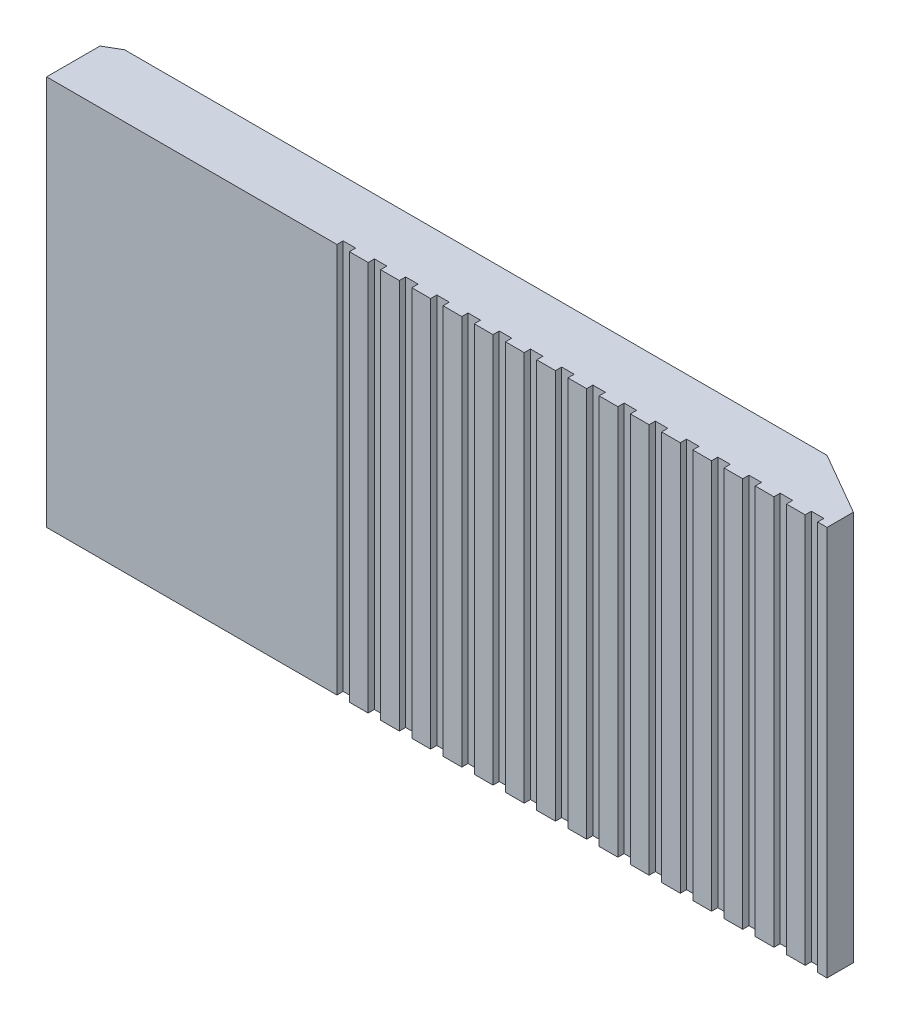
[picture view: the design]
ISO-10303-21;
HEADER;
FILE_DESCRIPTION(('STEP AP214'),'2;1');
FILE_NAME('part.step','',(''),(''),'','','');
FILE_SCHEMA(('AUTOMOTIVE_DESIGN { 1 0 10303 214 1 1 1 1 }'));
ENDSEC;
DATA;
#1=APPLICATION_CONTEXT('core data for automotive mechanical design processes');
#2=APPLICATION_PROTOCOL_DEFINITION('international standard','automotive_design',2000,#1);
#3=PRODUCT_CONTEXT('',#1,'mechanical');
#4=PRODUCT('Part','Part','',(#3));
#5=PRODUCT_RELATED_PRODUCT_CATEGORY('part','',(#4));
#6=PRODUCT_DEFINITION_FORMATION('','',#4);
#7=PRODUCT_DEFINITION_CONTEXT('part definition',#1,'design');
#8=PRODUCT_DEFINITION('design','',#6,#7);
#9=PRODUCT_DEFINITION_SHAPE('','',#8);
#10=(LENGTH_UNIT() NAMED_UNIT(*) SI_UNIT(.MILLI.,.METRE.));
#11=(NAMED_UNIT(*) PLANE_ANGLE_UNIT() SI_UNIT($,.RADIAN.));
#12=(NAMED_UNIT(*) SI_UNIT($,.STERADIAN.) SOLID_ANGLE_UNIT());
#13=UNCERTAINTY_MEASURE_WITH_UNIT(LENGTH_MEASURE(1.E-05),#10,'distance_accuracy_value','');
#14=(GEOMETRIC_REPRESENTATION_CONTEXT(3) GLOBAL_UNCERTAINTY_ASSIGNED_CONTEXT((#13)) GLOBAL_UNIT_ASSIGNED_CONTEXT((#10,
#11,#12)) REPRESENTATION_CONTEXT('',''));
#15=CARTESIAN_POINT('',(0.,0.,0.));
#16=DIRECTION('',(0.,0.,1.));
#17=DIRECTION('',(1.,0.,0.));
#18=AXIS2_PLACEMENT_3D('',#15,#16,#17);
#19=CARTESIAN_POINT('',(0.,0.,4.));
#20=DIRECTION('',(0.,0.,-1.));
#21=DIRECTION('',(-1.,0.,0.));
#22=AXIS2_PLACEMENT_3D('',#19,#20,#21);
#23=PLANE('',#22);
#24=DIRECTION('',(-1.,0.,0.));
#25=VECTOR('',#24,1.);
#26=CARTESIAN_POINT('',(-25.,12.5,4.));
#27=LINE('',#26,#25);
#28=CARTESIAN_POINT('',(23.6,12.5,4.));
#29=VERTEX_POINT('',#28);
#30=CARTESIAN_POINT('',(22.4,12.5,4.));
#31=VERTEX_POINT('',#30);
#32=EDGE_CURVE('E582',#29,#31,#27,.T.);
#33=ORIENTED_EDGE('',*,*,#32,.T.);
#34=DIRECTION('',(0.,1.,0.));
#35=VECTOR('',#34,1.);
#36=CARTESIAN_POINT('',(22.4,-12.501,4.));
#37=LINE('',#36,#35);
#38=CARTESIAN_POINT('',(22.4,-12.5,4.));
#39=VERTEX_POINT('',#38);
#40=EDGE_CURVE('E504',#39,#31,#37,.T.);
#41=ORIENTED_EDGE('',*,*,#40,.F.);
#42=DIRECTION('',(1.,0.,0.));
#43=VECTOR('',#42,1.);
#44=CARTESIAN_POINT('',(-25.,-12.5,4.));
#45=LINE('',#44,#43);
#46=CARTESIAN_POINT('',(23.6,-12.5,4.));
#47=VERTEX_POINT('',#46);
#48=EDGE_CURVE('E520',#39,#47,#45,.T.);
#49=ORIENTED_EDGE('',*,*,#48,.T.);
#50=DIRECTION('',(0.,-1.,0.));
#51=VECTOR('',#50,1.);
#52=CARTESIAN_POINT('',(23.6,-12.501,4.));
#53=LINE('',#52,#51);
#54=EDGE_CURVE('E643',#29,#47,#53,.T.);
#55=ORIENTED_EDGE('',*,*,#54,.F.);
#56=EDGE_LOOP('',(#33,#41,#49,#55));
#57=FACE_BOUND('',#56,.T.);
#58=ADVANCED_FACE('F34',(#57),#23,.F.);
#59=CARTESIAN_POINT('',(20.4,-12.5,4.));
#60=VERTEX_POINT('',#59);
#61=CARTESIAN_POINT('',(21.6,-12.5,4.));
#62=VERTEX_POINT('',#61);
#63=EDGE_CURVE('E511',#60,#62,#45,.T.);
#64=ORIENTED_EDGE('',*,*,#63,.T.);
#65=DIRECTION('',(0.,-1.,0.));
#66=VECTOR('',#65,1.);
#67=CARTESIAN_POINT('',(21.6,-12.501,4.));
#68=LINE('',#67,#66);
#69=CARTESIAN_POINT('',(21.6,12.5,4.));
#70=VERTEX_POINT('',#69);
#71=EDGE_CURVE('E493',#70,#62,#68,.T.);
#72=ORIENTED_EDGE('',*,*,#71,.F.);
#73=CARTESIAN_POINT('',(20.4,12.5,4.));
#74=VERTEX_POINT('',#73);
#75=EDGE_CURVE('E587',#70,#74,#27,.T.);
#76=ORIENTED_EDGE('',*,*,#75,.T.);
#77=DIRECTION('',(0.,1.,0.));
#78=VECTOR('',#77,1.);
#79=CARTESIAN_POINT('',(20.4,-12.501,4.));
#80=LINE('',#79,#78);
#81=EDGE_CURVE('E518',#60,#74,#80,.T.);
#82=ORIENTED_EDGE('',*,*,#81,.F.);
#83=EDGE_LOOP('',(#64,#72,#76,#82));
#84=FACE_BOUND('',#83,.T.);
#85=ADVANCED_FACE('F517',(#84),#23,.F.);
#86=CARTESIAN_POINT('',(18.4,-12.5,4.));
#87=VERTEX_POINT('',#86);
#88=CARTESIAN_POINT('',(19.6,-12.5,4.));
#89=VERTEX_POINT('',#88);
#90=EDGE_CURVE('E519',#87,#89,#45,.T.);
#91=ORIENTED_EDGE('',*,*,#90,.T.);
#92=DIRECTION('',(0.,-1.,0.));
#93=VECTOR('',#92,1.);
#94=CARTESIAN_POINT('',(19.6,-12.501,4.));
#95=LINE('',#94,#93);
#96=CARTESIAN_POINT('',(19.6,12.5,4.));
#97=VERTEX_POINT('',#96);
#98=EDGE_CURVE('E911',#97,#89,#95,.T.);
#99=ORIENTED_EDGE('',*,*,#98,.F.);
#100=CARTESIAN_POINT('',(18.4,12.5,4.));
#101=VERTEX_POINT('',#100);
#102=EDGE_CURVE('E1127',#97,#101,#27,.T.);
#103=ORIENTED_EDGE('',*,*,#102,.T.);
#104=DIRECTION('',(0.,1.,0.));
#105=VECTOR('',#104,1.);
#106=CARTESIAN_POINT('',(18.4,-12.501,4.));
#107=LINE('',#106,#105);
#108=EDGE_CURVE('E928',#87,#101,#107,.T.);
#109=ORIENTED_EDGE('',*,*,#108,.F.);
#110=EDGE_LOOP('',(#91,#99,#103,#109));
#111=FACE_BOUND('',#110,.T.);
#112=ADVANCED_FACE('F1012',(#111),#23,.F.);
#113=CARTESIAN_POINT('',(16.4,-12.5,4.));
#114=VERTEX_POINT('',#113);
#115=CARTESIAN_POINT('',(17.6,-12.5,4.));
#116=VERTEX_POINT('',#115);
#117=EDGE_CURVE('E523',#114,#116,#45,.T.);
#118=ORIENTED_EDGE('',*,*,#117,.T.);
#119=DIRECTION('',(0.,-1.,0.));
#120=VECTOR('',#119,1.);
#121=CARTESIAN_POINT('',(17.6,-12.501,4.));
#122=LINE('',#121,#120);
#123=CARTESIAN_POINT('',(17.6,12.5,4.));
#124=VERTEX_POINT('',#123);
#125=EDGE_CURVE('E889',#124,#116,#122,.T.);
#126=ORIENTED_EDGE('',*,*,#125,.F.);
#127=CARTESIAN_POINT('',(16.4,12.5,4.));
#128=VERTEX_POINT('',#127);
#129=EDGE_CURVE('E1125',#124,#128,#27,.T.);
#130=ORIENTED_EDGE('',*,*,#129,.T.);
#131=DIRECTION('',(0.,1.,0.));
#132=VECTOR('',#131,1.);
#133=CARTESIAN_POINT('',(16.4,-12.501,4.));
#134=LINE('',#133,#132);
#135=EDGE_CURVE('E906',#114,#128,#134,.T.);
#136=ORIENTED_EDGE('',*,*,#135,.F.);
#137=EDGE_LOOP('',(#118,#126,#130,#136));
#138=FACE_BOUND('',#137,.T.);
#139=ADVANCED_FACE('F1107',(#138),#23,.F.);
#140=CARTESIAN_POINT('',(14.4,-12.5,4.));
#141=VERTEX_POINT('',#140);
#142=CARTESIAN_POINT('',(15.6,-12.5,4.));
#143=VERTEX_POINT('',#142);
#144=EDGE_CURVE('E1092',#141,#143,#45,.T.);
#145=ORIENTED_EDGE('',*,*,#144,.T.);
#146=DIRECTION('',(0.,-1.,0.));
#147=VECTOR('',#146,1.);
#148=CARTESIAN_POINT('',(15.6,-12.501,4.));
#149=LINE('',#148,#147);
#150=CARTESIAN_POINT('',(15.6,12.5,4.));
#151=VERTEX_POINT('',#150);
#152=EDGE_CURVE('E867',#151,#143,#149,.T.);
#153=ORIENTED_EDGE('',*,*,#152,.F.);
#154=CARTESIAN_POINT('',(14.4,12.5,4.));
#155=VERTEX_POINT('',#154);
#156=EDGE_CURVE('E1128',#151,#155,#27,.T.);
#157=ORIENTED_EDGE('',*,*,#156,.T.);
#158=DIRECTION('',(0.,1.,0.));
#159=VECTOR('',#158,1.);
#160=CARTESIAN_POINT('',(14.4,-12.501,4.));
#161=LINE('',#160,#159);
#162=EDGE_CURVE('E884',#141,#155,#161,.T.);
#163=ORIENTED_EDGE('',*,*,#162,.F.);
#164=EDGE_LOOP('',(#145,#153,#157,#163));
#165=FACE_BOUND('',#164,.T.);
#166=ADVANCED_FACE('F1300',(#165),#23,.F.);
#167=CARTESIAN_POINT('',(12.4,-12.5,4.));
#168=VERTEX_POINT('',#167);
#169=CARTESIAN_POINT('',(13.6,-12.5,4.));
#170=VERTEX_POINT('',#169);
#171=EDGE_CURVE('E1086',#168,#170,#45,.T.);
#172=ORIENTED_EDGE('',*,*,#171,.T.);
#173=DIRECTION('',(0.,-1.,0.));
#174=VECTOR('',#173,1.);
#175=CARTESIAN_POINT('',(13.6,-12.501,4.));
#176=LINE('',#175,#174);
#177=CARTESIAN_POINT('',(13.6,12.5,4.));
#178=VERTEX_POINT('',#177);
#179=EDGE_CURVE('E845',#178,#170,#176,.T.);
#180=ORIENTED_EDGE('',*,*,#179,.F.);
#181=CARTESIAN_POINT('',(12.4,12.5,4.));
#182=VERTEX_POINT('',#181);
#183=EDGE_CURVE('E1131',#178,#182,#27,.T.);
#184=ORIENTED_EDGE('',*,*,#183,.T.);
#185=DIRECTION('',(0.,1.,0.));
#186=VECTOR('',#185,1.);
#187=CARTESIAN_POINT('',(12.4,-12.501,4.));
#188=LINE('',#187,#186);
#189=EDGE_CURVE('E862',#168,#182,#188,.T.);
#190=ORIENTED_EDGE('',*,*,#189,.F.);
#191=EDGE_LOOP('',(#172,#180,#184,#190));
#192=FACE_BOUND('',#191,.T.);
#193=ADVANCED_FACE('F1285',(#192),#23,.F.);
#194=CARTESIAN_POINT('',(10.4,-12.5,4.));
#195=VERTEX_POINT('',#194);
#196=CARTESIAN_POINT('',(11.6,-12.5,4.));
#197=VERTEX_POINT('',#196);
#198=EDGE_CURVE('E1080',#195,#197,#45,.T.);
#199=ORIENTED_EDGE('',*,*,#198,.T.);
#200=DIRECTION('',(0.,-1.,0.));
#201=VECTOR('',#200,1.);
#202=CARTESIAN_POINT('',(11.6,-12.501,4.));
#203=LINE('',#202,#201);
#204=CARTESIAN_POINT('',(11.6,12.5,4.));
#205=VERTEX_POINT('',#204);
#206=EDGE_CURVE('E823',#205,#197,#203,.T.);
#207=ORIENTED_EDGE('',*,*,#206,.F.);
#208=CARTESIAN_POINT('',(10.4,12.5,4.));
#209=VERTEX_POINT('',#208);
#210=EDGE_CURVE('E1134',#205,#209,#27,.T.);
#211=ORIENTED_EDGE('',*,*,#210,.T.);
#212=DIRECTION('',(0.,1.,0.));
#213=VECTOR('',#212,1.);
#214=CARTESIAN_POINT('',(10.4,-12.501,4.));
#215=LINE('',#214,#213);
#216=EDGE_CURVE('E840',#195,#209,#215,.T.);
#217=ORIENTED_EDGE('',*,*,#216,.F.);
#218=EDGE_LOOP('',(#199,#207,#211,#217));
#219=FACE_BOUND('',#218,.T.);
#220=ADVANCED_FACE('F1270',(#219),#23,.F.);
#221=CARTESIAN_POINT('',(8.4,-12.5,4.));
#222=VERTEX_POINT('',#221);
#223=CARTESIAN_POINT('',(9.6,-12.5,4.));
#224=VERTEX_POINT('',#223);
#225=EDGE_CURVE('E1074',#222,#224,#45,.T.);
#226=ORIENTED_EDGE('',*,*,#225,.T.);
#227=DIRECTION('',(0.,-1.,0.));
#228=VECTOR('',#227,1.);
#229=CARTESIAN_POINT('',(9.6,-12.501,4.));
#230=LINE('',#229,#228);
#231=CARTESIAN_POINT('',(9.6,12.5,4.));
#232=VERTEX_POINT('',#231);
#233=EDGE_CURVE('E801',#232,#224,#230,.T.);
#234=ORIENTED_EDGE('',*,*,#233,.F.);
#235=CARTESIAN_POINT('',(8.4,12.5,4.));
#236=VERTEX_POINT('',#235);
#237=EDGE_CURVE('E1137',#232,#236,#27,.T.);
#238=ORIENTED_EDGE('',*,*,#237,.T.);
#239=DIRECTION('',(0.,1.,0.));
#240=VECTOR('',#239,1.);
#241=CARTESIAN_POINT('',(8.4,-12.501,4.));
#242=LINE('',#241,#240);
#243=EDGE_CURVE('E818',#222,#236,#242,.T.);
#244=ORIENTED_EDGE('',*,*,#243,.F.);
#245=EDGE_LOOP('',(#226,#234,#238,#244));
#246=FACE_BOUND('',#245,.T.);
#247=ADVANCED_FACE('F1255',(#246),#23,.F.);
#248=CARTESIAN_POINT('',(6.4,-12.5,4.));
#249=VERTEX_POINT('',#248);
#250=CARTESIAN_POINT('',(7.6,-12.5,4.));
#251=VERTEX_POINT('',#250);
#252=EDGE_CURVE('E1068',#249,#251,#45,.T.);
#253=ORIENTED_EDGE('',*,*,#252,.T.);
#254=DIRECTION('',(0.,-1.,0.));
#255=VECTOR('',#254,1.);
#256=CARTESIAN_POINT('',(7.6,-12.501,4.));
#257=LINE('',#256,#255);
#258=CARTESIAN_POINT('',(7.6,12.5,4.));
#259=VERTEX_POINT('',#258);
#260=EDGE_CURVE('E779',#259,#251,#257,.T.);
#261=ORIENTED_EDGE('',*,*,#260,.F.);
#262=CARTESIAN_POINT('',(6.4,12.5,4.));
#263=VERTEX_POINT('',#262);
#264=EDGE_CURVE('E1140',#259,#263,#27,.T.);
#265=ORIENTED_EDGE('',*,*,#264,.T.);
#266=DIRECTION('',(0.,1.,0.));
#267=VECTOR('',#266,1.);
#268=CARTESIAN_POINT('',(6.4,-12.501,4.));
#269=LINE('',#268,#267);
#270=EDGE_CURVE('E796',#249,#263,#269,.T.);
#271=ORIENTED_EDGE('',*,*,#270,.F.);
#272=EDGE_LOOP('',(#253,#261,#265,#271));
#273=FACE_BOUND('',#272,.T.);
#274=ADVANCED_FACE('F1240',(#273),#23,.F.);
#275=CARTESIAN_POINT('',(4.4,-12.5,4.));
#276=VERTEX_POINT('',#275);
#277=CARTESIAN_POINT('',(5.6,-12.5,4.));
#278=VERTEX_POINT('',#277);
#279=EDGE_CURVE('E1062',#276,#278,#45,.T.);
#280=ORIENTED_EDGE('',*,*,#279,.T.);
#281=DIRECTION('',(0.,-1.,0.));
#282=VECTOR('',#281,1.);
#283=CARTESIAN_POINT('',(5.6,-12.501,4.));
#284=LINE('',#283,#282);
#285=CARTESIAN_POINT('',(5.6,12.5,4.));
#286=VERTEX_POINT('',#285);
#287=EDGE_CURVE('E757',#286,#278,#284,.T.);
#288=ORIENTED_EDGE('',*,*,#287,.F.);
#289=CARTESIAN_POINT('',(4.4,12.5,4.));
#290=VERTEX_POINT('',#289);
#291=EDGE_CURVE('E1143',#286,#290,#27,.T.);
#292=ORIENTED_EDGE('',*,*,#291,.T.);
#293=DIRECTION('',(0.,1.,0.));
#294=VECTOR('',#293,1.);
#295=CARTESIAN_POINT('',(4.4,-12.501,4.));
#296=LINE('',#295,#294);
#297=EDGE_CURVE('E774',#276,#290,#296,.T.);
#298=ORIENTED_EDGE('',*,*,#297,.F.);
#299=EDGE_LOOP('',(#280,#288,#292,#298));
#300=FACE_BOUND('',#299,.T.);
#301=ADVANCED_FACE('F1225',(#300),#23,.F.);
#302=CARTESIAN_POINT('',(2.4,-12.5,4.));
#303=VERTEX_POINT('',#302);
#304=CARTESIAN_POINT('',(3.6,-12.5,4.));
#305=VERTEX_POINT('',#304);
#306=EDGE_CURVE('E1056',#303,#305,#45,.T.);
#307=ORIENTED_EDGE('',*,*,#306,.T.);
#308=DIRECTION('',(0.,-1.,0.));
#309=VECTOR('',#308,1.);
#310=CARTESIAN_POINT('',(3.6,-12.501,4.));
#311=LINE('',#310,#309);
#312=CARTESIAN_POINT('',(3.6,12.5,4.));
#313=VERTEX_POINT('',#312);
#314=EDGE_CURVE('E735',#313,#305,#311,.T.);
#315=ORIENTED_EDGE('',*,*,#314,.F.);
#316=CARTESIAN_POINT('',(2.4,12.5,4.));
#317=VERTEX_POINT('',#316);
#318=EDGE_CURVE('E1146',#313,#317,#27,.T.);
#319=ORIENTED_EDGE('',*,*,#318,.T.);
#320=DIRECTION('',(0.,1.,0.));
#321=VECTOR('',#320,1.);
#322=CARTESIAN_POINT('',(2.4,-12.501,4.));
#323=LINE('',#322,#321);
#324=EDGE_CURVE('E752',#303,#317,#323,.T.);
#325=ORIENTED_EDGE('',*,*,#324,.F.);
#326=EDGE_LOOP('',(#307,#315,#319,#325));
#327=FACE_BOUND('',#326,.T.);
#328=ADVANCED_FACE('F1210',(#327),#23,.F.);
#329=CARTESIAN_POINT('',(0.399999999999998,-12.5,4.));
#330=VERTEX_POINT('',#329);
#331=CARTESIAN_POINT('',(1.6,-12.5,4.));
#332=VERTEX_POINT('',#331);
#333=EDGE_CURVE('E1050',#330,#332,#45,.T.);
#334=ORIENTED_EDGE('',*,*,#333,.T.);
#335=DIRECTION('',(0.,-1.,0.));
#336=VECTOR('',#335,1.);
#337=CARTESIAN_POINT('',(1.6,-12.501,4.));
#338=LINE('',#337,#336);
#339=CARTESIAN_POINT('',(1.6,12.5,4.));
#340=VERTEX_POINT('',#339);
#341=EDGE_CURVE('E713',#340,#332,#338,.T.);
#342=ORIENTED_EDGE('',*,*,#341,.F.);
#343=CARTESIAN_POINT('',(0.399999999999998,12.5,4.));
#344=VERTEX_POINT('',#343);
#345=EDGE_CURVE('E1149',#340,#344,#27,.T.);
#346=ORIENTED_EDGE('',*,*,#345,.T.);
#347=DIRECTION('',(0.,1.,0.));
#348=VECTOR('',#347,1.);
#349=CARTESIAN_POINT('',(0.399999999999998,-12.501,4.));
#350=LINE('',#349,#348);
#351=EDGE_CURVE('E730',#330,#344,#350,.T.);
#352=ORIENTED_EDGE('',*,*,#351,.F.);
#353=EDGE_LOOP('',(#334,#342,#346,#352));
#354=FACE_BOUND('',#353,.T.);
#355=ADVANCED_FACE('F1195',(#354),#23,.F.);
#356=CARTESIAN_POINT('',(-1.6,-12.5,4.));
#357=VERTEX_POINT('',#356);
#358=CARTESIAN_POINT('',(-0.400000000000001,-12.5,4.));
#359=VERTEX_POINT('',#358);
#360=EDGE_CURVE('E1045',#357,#359,#45,.T.);
#361=ORIENTED_EDGE('',*,*,#360,.T.);
#362=DIRECTION('',(0.,-1.,0.));
#363=VECTOR('',#362,1.);
#364=CARTESIAN_POINT('',(-0.400000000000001,-12.501,4.));
#365=LINE('',#364,#363);
#366=CARTESIAN_POINT('',(-0.400000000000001,12.5,4.));
#367=VERTEX_POINT('',#366);
#368=EDGE_CURVE('E691',#367,#359,#365,.T.);
#369=ORIENTED_EDGE('',*,*,#368,.F.);
#370=CARTESIAN_POINT('',(-1.6,12.5,4.));
#371=VERTEX_POINT('',#370);
#372=EDGE_CURVE('E1152',#367,#371,#27,.T.);
#373=ORIENTED_EDGE('',*,*,#372,.T.);
#374=DIRECTION('',(0.,1.,0.));
#375=VECTOR('',#374,1.);
#376=CARTESIAN_POINT('',(-1.6,-12.501,4.));
#377=LINE('',#376,#375);
#378=EDGE_CURVE('E708',#357,#371,#377,.T.);
#379=ORIENTED_EDGE('',*,*,#378,.F.);
#380=EDGE_LOOP('',(#361,#369,#373,#379));
#381=FACE_BOUND('',#380,.T.);
#382=ADVANCED_FACE('F1034',(#381),#23,.F.);
#383=CARTESIAN_POINT('',(-3.6,-12.5,4.));
#384=VERTEX_POINT('',#383);
#385=CARTESIAN_POINT('',(-2.4,-12.5,4.));
#386=VERTEX_POINT('',#385);
#387=EDGE_CURVE('E1043',#384,#386,#45,.T.);
#388=ORIENTED_EDGE('',*,*,#387,.T.);
#389=DIRECTION('',(0.,-1.,0.));
#390=VECTOR('',#389,1.);
#391=CARTESIAN_POINT('',(-2.4,-12.501,4.));
#392=LINE('',#391,#390);
#393=CARTESIAN_POINT('',(-2.4,12.5,4.));
#394=VERTEX_POINT('',#393);
#395=EDGE_CURVE('E669',#394,#386,#392,.T.);
#396=ORIENTED_EDGE('',*,*,#395,.F.);
#397=CARTESIAN_POINT('',(-3.6,12.5,4.));
#398=VERTEX_POINT('',#397);
#399=EDGE_CURVE('E591',#394,#398,#27,.T.);
#400=ORIENTED_EDGE('',*,*,#399,.T.);
#401=DIRECTION('',(0.,1.,0.));
#402=VECTOR('',#401,1.);
#403=CARTESIAN_POINT('',(-3.6,-12.501,4.));
#404=LINE('',#403,#402);
#405=EDGE_CURVE('E686',#384,#398,#404,.T.);
#406=ORIENTED_EDGE('',*,*,#405,.F.);
#407=EDGE_LOOP('',(#388,#396,#400,#406));
#408=FACE_BOUND('',#407,.T.);
#409=ADVANCED_FACE('F1029',(#408),#23,.F.);
#410=CARTESIAN_POINT('',(-5.6,-12.5,4.));
#411=VERTEX_POINT('',#410);
#412=CARTESIAN_POINT('',(-4.4,-12.5,4.));
#413=VERTEX_POINT('',#412);
#414=EDGE_CURVE('E530',#411,#413,#45,.T.);
#415=ORIENTED_EDGE('',*,*,#414,.T.);
#416=DIRECTION('',(0.,-1.,0.));
#417=VECTOR('',#416,1.);
#418=CARTESIAN_POINT('',(-4.4,-12.501,4.));
#419=LINE('',#418,#417);
#420=CARTESIAN_POINT('',(-4.4,12.5,4.));
#421=VERTEX_POINT('',#420);
#422=EDGE_CURVE('E648',#421,#413,#419,.T.);
#423=ORIENTED_EDGE('',*,*,#422,.F.);
#424=CARTESIAN_POINT('',(-5.6,12.5,4.));
#425=VERTEX_POINT('',#424);
#426=EDGE_CURVE('E589',#421,#425,#27,.T.);
#427=ORIENTED_EDGE('',*,*,#426,.T.);
#428=DIRECTION('',(0.,1.,0.));
#429=VECTOR('',#428,1.);
#430=CARTESIAN_POINT('',(-5.6,-12.501,4.));
#431=LINE('',#430,#429);
#432=EDGE_CURVE('E664',#411,#425,#431,.T.);
#433=ORIENTED_EDGE('',*,*,#432,.F.);
#434=EDGE_LOOP('',(#415,#423,#427,#433));
#435=FACE_BOUND('',#434,.T.);
#436=ADVANCED_FACE('F1024',(#435),#23,.F.);
#437=CARTESIAN_POINT('',(25.,12.5,4.));
#438=VERTEX_POINT('',#437);
#439=CARTESIAN_POINT('',(24.4,12.5,4.));
#440=VERTEX_POINT('',#439);
#441=EDGE_CURVE('E580',#438,#440,#27,.T.);
#442=ORIENTED_EDGE('',*,*,#441,.T.);
#443=DIRECTION('',(0.,1.,0.));
#444=VECTOR('',#443,1.);
#445=CARTESIAN_POINT('',(24.4,-12.501,4.));
#446=LINE('',#445,#444);
#447=CARTESIAN_POINT('',(24.4,-12.5,4.));
#448=VERTEX_POINT('',#447);
#449=EDGE_CURVE('E641',#448,#440,#446,.T.);
#450=ORIENTED_EDGE('',*,*,#449,.F.);
#451=CARTESIAN_POINT('',(25.,-12.5,4.));
#452=VERTEX_POINT('',#451);
#453=EDGE_CURVE('E524',#448,#452,#45,.T.);
#454=ORIENTED_EDGE('',*,*,#453,.T.);
#455=DIRECTION('',(0.,1.,0.));
#456=VECTOR('',#455,1.);
#457=CARTESIAN_POINT('',(25.,-12.5,4.));
#458=LINE('',#457,#456);
#459=EDGE_CURVE('E538',#452,#438,#458,.T.);
#460=ORIENTED_EDGE('',*,*,#459,.T.);
#461=EDGE_LOOP('',(#442,#450,#454,#460));
#462=FACE_BOUND('',#461,.T.);
#463=ADVANCED_FACE('F1016',(#462),#23,.F.);
#464=CARTESIAN_POINT('',(0.,0.,0.));
#465=DIRECTION('',(0.,0.,-1.));
#466=DIRECTION('',(-1.,0.,0.));
#467=AXIS2_PLACEMENT_3D('',#464,#465,#466);
#468=PLANE('',#467);
#469=DIRECTION('',(1.,0.,0.));
#470=VECTOR('',#469,1.);
#471=CARTESIAN_POINT('',(-25.,-12.5,0.));
#472=LINE('',#471,#470);
#473=CARTESIAN_POINT('',(-24.,-12.5,0.));
#474=VERTEX_POINT('',#473);
#475=CARTESIAN_POINT('',(21.,-12.5,0.));
#476=VERTEX_POINT('',#475);
#477=EDGE_CURVE('E535',#474,#476,#472,.T.);
#478=ORIENTED_EDGE('',*,*,#477,.F.);
#479=DIRECTION('',(0.,1.,0.));
#480=VECTOR('',#479,1.);
#481=CARTESIAN_POINT('',(-24.,12.5,0.));
#482=LINE('',#481,#480);
#483=CARTESIAN_POINT('',(-24.,12.5,0.));
#484=VERTEX_POINT('',#483);
#485=EDGE_CURVE('E42',#474,#484,#482,.T.);
#486=ORIENTED_EDGE('',*,*,#485,.T.);
#487=DIRECTION('',(-1.,0.,0.));
#488=VECTOR('',#487,1.);
#489=CARTESIAN_POINT('',(-25.,12.5,0.));
#490=LINE('',#489,#488);
#491=CARTESIAN_POINT('',(21.,12.5,0.));
#492=VERTEX_POINT('',#491);
#493=EDGE_CURVE('E533',#492,#484,#490,.T.);
#494=ORIENTED_EDGE('',*,*,#493,.F.);
#495=DIRECTION('',(0.,-1.,0.));
#496=VECTOR('',#495,1.);
#497=CARTESIAN_POINT('',(21.,-12.5,0.));
#498=LINE('',#497,#496);
#499=EDGE_CURVE('E554',#492,#476,#498,.T.);
#500=ORIENTED_EDGE('',*,*,#499,.T.);
#501=EDGE_LOOP('',(#478,#486,#494,#500));
#502=FACE_BOUND('',#501,.T.);
#503=DIRECTION('',(1.,0.,0.));
#504=VECTOR('',#503,1.);
#505=CARTESIAN_POINT('',(15.,5.,0.));
#506=LINE('',#505,#504);
#507=CARTESIAN_POINT('',(5.,5.,0.));
#508=VERTEX_POINT('',#507);
#509=CARTESIAN_POINT('',(15.,5.,0.));
#510=VERTEX_POINT('',#509);
#511=EDGE_CURVE('E611',#508,#510,#506,.T.);
#512=ORIENTED_EDGE('',*,*,#511,.F.);
#513=DIRECTION('',(0.,1.,0.));
#514=VECTOR('',#513,1.);
#515=CARTESIAN_POINT('',(5.,-5.,0.));
#516=LINE('',#515,#514);
#517=CARTESIAN_POINT('',(5.,-5.,0.));
#518=VERTEX_POINT('',#517);
#519=EDGE_CURVE('E613',#518,#508,#516,.T.);
#520=ORIENTED_EDGE('',*,*,#519,.F.);
#521=DIRECTION('',(-1.,0.,0.));
#522=VECTOR('',#521,1.);
#523=CARTESIAN_POINT('',(15.,-5.,0.));
#524=LINE('',#523,#522);
#525=CARTESIAN_POINT('',(15.,-5.,0.));
#526=VERTEX_POINT('',#525);
#527=EDGE_CURVE('E605',#526,#518,#524,.T.);
#528=ORIENTED_EDGE('',*,*,#527,.F.);
#529=DIRECTION('',(0.,-1.,0.));
#530=VECTOR('',#529,1.);
#531=CARTESIAN_POINT('',(15.,-5.,0.));
#532=LINE('',#531,#530);
#533=EDGE_CURVE('E608',#510,#526,#532,.T.);
#534=ORIENTED_EDGE('',*,*,#533,.F.);
#535=EDGE_LOOP('',(#512,#520,#528,#534));
#536=FACE_BOUND('',#535,.T.);
#537=ADVANCED_FACE('F998',(#502,#536),#468,.T.);
#538=CARTESIAN_POINT('',(25.,-12.5,4.));
#539=DIRECTION('',(-1.,0.,0.));
#540=DIRECTION('',(0.,0.,1.));
#541=AXIS2_PLACEMENT_3D('',#538,#539,#540);
#542=PLANE('',#541);
#543=DIRECTION('',(0.,0.,-1.));
#544=VECTOR('',#543,1.);
#545=CARTESIAN_POINT('',(25.,-12.5,4.));
#546=LINE('',#545,#544);
#547=CARTESIAN_POINT('',(25.,-12.5,2.3094010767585));
#548=VERTEX_POINT('',#547);
#549=EDGE_CURVE('E529',#452,#548,#546,.T.);
#550=ORIENTED_EDGE('',*,*,#549,.T.);
#551=DIRECTION('',(0.,1.,0.));
#552=VECTOR('',#551,1.);
#553=CARTESIAN_POINT('',(25.,12.5,2.3094010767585));
#554=LINE('',#553,#552);
#555=CARTESIAN_POINT('',(25.,12.5,2.3094010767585));
#556=VERTEX_POINT('',#555);
#557=EDGE_CURVE('E549',#548,#556,#554,.T.);
#558=ORIENTED_EDGE('',*,*,#557,.T.);
#559=DIRECTION('',(0.,0.,-1.));
#560=VECTOR('',#559,1.);
#561=CARTESIAN_POINT('',(25.,12.5,4.));
#562=LINE('',#561,#560);
#563=EDGE_CURVE('E546',#438,#556,#562,.T.);
#564=ORIENTED_EDGE('',*,*,#563,.F.);
#565=ORIENTED_EDGE('',*,*,#459,.F.);
#566=EDGE_LOOP('',(#550,#558,#564,#565));
#567=FACE_BOUND('',#566,.T.);
#568=ADVANCED_FACE('F991',(#567),#542,.F.);
#569=CARTESIAN_POINT('',(-25.,12.5,4.));
#570=DIRECTION('',(0.,-1.,0.));
#571=DIRECTION('',(0.,0.,-1.));
#572=AXIS2_PLACEMENT_3D('',#569,#570,#571);
#573=PLANE('',#572);
#574=ORIENTED_EDGE('',*,*,#493,.T.);
#575=DIRECTION('',(-0.866025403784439,0.,0.5));
#576=VECTOR('',#575,1.);
#577=CARTESIAN_POINT('',(-25.,12.5,0.57735026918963));
#578=LINE('',#577,#576);
#579=CARTESIAN_POINT('',(-25.,12.5,0.57735026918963));
#580=VERTEX_POINT('',#579);
#581=EDGE_CURVE('E11',#484,#580,#578,.T.);
#582=ORIENTED_EDGE('',*,*,#581,.T.);
#583=DIRECTION('',(0.,0.,-1.));
#584=VECTOR('',#583,1.);
#585=CARTESIAN_POINT('',(-25.,12.5,4.));
#586=LINE('',#585,#584);
#587=CARTESIAN_POINT('',(-25.,12.5,4.));
#588=VERTEX_POINT('',#587);
#589=EDGE_CURVE('E543',#588,#580,#586,.T.);
#590=ORIENTED_EDGE('',*,*,#589,.F.);
#591=CARTESIAN_POINT('',(-6.4,12.5,4.));
#592=VERTEX_POINT('',#591);
#593=EDGE_CURVE('E579',#592,#588,#27,.T.);
#594=ORIENTED_EDGE('',*,*,#593,.F.);
#595=DIRECTION('',(0.,0.,1.));
#596=VECTOR('',#595,1.);
#597=CARTESIAN_POINT('',(-6.4,12.5,4.4));
#598=LINE('',#597,#596);
#599=CARTESIAN_POINT('',(-6.4,12.5,3.6));
#600=VERTEX_POINT('',#599);
#601=EDGE_CURVE('E652',#600,#592,#598,.T.);
#602=ORIENTED_EDGE('',*,*,#601,.F.);
#603=DIRECTION('',(-1.,0.,0.));
#604=VECTOR('',#603,1.);
#605=CARTESIAN_POINT('',(-6.4,12.5,3.6));
#606=LINE('',#605,#604);
#607=CARTESIAN_POINT('',(-5.6,12.5,3.6));
#608=VERTEX_POINT('',#607);
#609=EDGE_CURVE('E655',#608,#600,#606,.T.);
#610=ORIENTED_EDGE('',*,*,#609,.F.);
#611=DIRECTION('',(0.,0.,-1.));
#612=VECTOR('',#611,1.);
#613=CARTESIAN_POINT('',(-5.6,12.5,4.4));
#614=LINE('',#613,#612);
#615=EDGE_CURVE('E658',#425,#608,#614,.T.);
#616=ORIENTED_EDGE('',*,*,#615,.F.);
#617=ORIENTED_EDGE('',*,*,#426,.F.);
#618=DIRECTION('',(0.,0.,1.));
#619=VECTOR('',#618,1.);
#620=CARTESIAN_POINT('',(-4.4,12.5,4.4));
#621=LINE('',#620,#619);
#622=CARTESIAN_POINT('',(-4.4,12.5,3.6));
#623=VERTEX_POINT('',#622);
#624=EDGE_CURVE('E673',#623,#421,#621,.T.);
#625=ORIENTED_EDGE('',*,*,#624,.F.);
#626=DIRECTION('',(-1.,0.,0.));
#627=VECTOR('',#626,1.);
#628=CARTESIAN_POINT('',(-4.4,12.5,3.6));
#629=LINE('',#628,#627);
#630=CARTESIAN_POINT('',(-3.6,12.5,3.6));
#631=VERTEX_POINT('',#630);
#632=EDGE_CURVE('E676',#631,#623,#629,.T.);
#633=ORIENTED_EDGE('',*,*,#632,.F.);
#634=DIRECTION('',(0.,0.,-1.));
#635=VECTOR('',#634,1.);
#636=CARTESIAN_POINT('',(-3.6,12.5,4.4));
#637=LINE('',#636,#635);
#638=EDGE_CURVE('E679',#398,#631,#637,.T.);
#639=ORIENTED_EDGE('',*,*,#638,.F.);
#640=ORIENTED_EDGE('',*,*,#399,.F.);
#641=DIRECTION('',(0.,0.,1.));
#642=VECTOR('',#641,1.);
#643=CARTESIAN_POINT('',(-2.4,12.5,4.4));
#644=LINE('',#643,#642);
#645=CARTESIAN_POINT('',(-2.4,12.5,3.6));
#646=VERTEX_POINT('',#645);
#647=EDGE_CURVE('E695',#646,#394,#644,.T.);
#648=ORIENTED_EDGE('',*,*,#647,.F.);
#649=DIRECTION('',(-1.,0.,0.));
#650=VECTOR('',#649,1.);
#651=CARTESIAN_POINT('',(-2.4,12.5,3.6));
#652=LINE('',#651,#650);
#653=CARTESIAN_POINT('',(-1.6,12.5,3.6));
#654=VERTEX_POINT('',#653);
#655=EDGE_CURVE('E698',#654,#646,#652,.T.);
#656=ORIENTED_EDGE('',*,*,#655,.F.);
#657=DIRECTION('',(0.,0.,-1.));
#658=VECTOR('',#657,1.);
#659=CARTESIAN_POINT('',(-1.6,12.5,4.4));
#660=LINE('',#659,#658);
#661=EDGE_CURVE('E701',#371,#654,#660,.T.);
#662=ORIENTED_EDGE('',*,*,#661,.F.);
#663=ORIENTED_EDGE('',*,*,#372,.F.);
#664=DIRECTION('',(0.,0.,1.));
#665=VECTOR('',#664,1.);
#666=CARTESIAN_POINT('',(-0.400000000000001,12.5,4.4));
#667=LINE('',#666,#665);
#668=CARTESIAN_POINT('',(-0.400000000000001,12.5,3.6));
#669=VERTEX_POINT('',#668);
#670=EDGE_CURVE('E717',#669,#367,#667,.T.);
#671=ORIENTED_EDGE('',*,*,#670,.F.);
#672=DIRECTION('',(-1.,0.,0.));
#673=VECTOR('',#672,1.);
#674=CARTESIAN_POINT('',(-0.400000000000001,12.5,3.6));
#675=LINE('',#674,#673);
#676=CARTESIAN_POINT('',(0.399999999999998,12.5,3.6));
#677=VERTEX_POINT('',#676);
#678=EDGE_CURVE('E720',#677,#669,#675,.T.);
#679=ORIENTED_EDGE('',*,*,#678,.F.);
#680=DIRECTION('',(0.,0.,-1.));
#681=VECTOR('',#680,1.);
#682=CARTESIAN_POINT('',(0.399999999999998,12.5,4.4));
#683=LINE('',#682,#681);
#684=EDGE_CURVE('E723',#344,#677,#683,.T.);
#685=ORIENTED_EDGE('',*,*,#684,.F.);
#686=ORIENTED_EDGE('',*,*,#345,.F.);
#687=DIRECTION('',(0.,0.,1.));
#688=VECTOR('',#687,1.);
#689=CARTESIAN_POINT('',(1.6,12.5,4.4));
#690=LINE('',#689,#688);
#691=CARTESIAN_POINT('',(1.6,12.5,3.6));
#692=VERTEX_POINT('',#691);
#693=EDGE_CURVE('E739',#692,#340,#690,.T.);
#694=ORIENTED_EDGE('',*,*,#693,.F.);
#695=DIRECTION('',(-1.,0.,0.));
#696=VECTOR('',#695,1.);
#697=CARTESIAN_POINT('',(1.6,12.5,3.6));
#698=LINE('',#697,#696);
#699=CARTESIAN_POINT('',(2.4,12.5,3.6));
#700=VERTEX_POINT('',#699);
#701=EDGE_CURVE('E742',#700,#692,#698,.T.);
#702=ORIENTED_EDGE('',*,*,#701,.F.);
#703=DIRECTION('',(0.,0.,-1.));
#704=VECTOR('',#703,1.);
#705=CARTESIAN_POINT('',(2.4,12.5,4.4));
#706=LINE('',#705,#704);
#707=EDGE_CURVE('E745',#317,#700,#706,.T.);
#708=ORIENTED_EDGE('',*,*,#707,.F.);
#709=ORIENTED_EDGE('',*,*,#318,.F.);
#710=DIRECTION('',(0.,0.,1.));
#711=VECTOR('',#710,1.);
#712=CARTESIAN_POINT('',(3.6,12.5,4.4));
#713=LINE('',#712,#711);
#714=CARTESIAN_POINT('',(3.6,12.5,3.6));
#715=VERTEX_POINT('',#714);
#716=EDGE_CURVE('E761',#715,#313,#713,.T.);
#717=ORIENTED_EDGE('',*,*,#716,.F.);
#718=DIRECTION('',(-1.,0.,0.));
#719=VECTOR('',#718,1.);
#720=CARTESIAN_POINT('',(3.6,12.5,3.6));
#721=LINE('',#720,#719);
#722=CARTESIAN_POINT('',(4.4,12.5,3.6));
#723=VERTEX_POINT('',#722);
#724=EDGE_CURVE('E764',#723,#715,#721,.T.);
#725=ORIENTED_EDGE('',*,*,#724,.F.);
#726=DIRECTION('',(0.,0.,-1.));
#727=VECTOR('',#726,1.);
#728=CARTESIAN_POINT('',(4.4,12.5,4.4));
#729=LINE('',#728,#727);
#730=EDGE_CURVE('E767',#290,#723,#729,.T.);
#731=ORIENTED_EDGE('',*,*,#730,.F.);
#732=ORIENTED_EDGE('',*,*,#291,.F.);
#733=DIRECTION('',(0.,0.,1.));
#734=VECTOR('',#733,1.);
#735=CARTESIAN_POINT('',(5.6,12.5,4.4));
#736=LINE('',#735,#734);
#737=CARTESIAN_POINT('',(5.6,12.5,3.6));
#738=VERTEX_POINT('',#737);
#739=EDGE_CURVE('E783',#738,#286,#736,.T.);
#740=ORIENTED_EDGE('',*,*,#739,.F.);
#741=DIRECTION('',(-1.,0.,0.));
#742=VECTOR('',#741,1.);
#743=CARTESIAN_POINT('',(5.6,12.5,3.6));
#744=LINE('',#743,#742);
#745=CARTESIAN_POINT('',(6.4,12.5,3.6));
#746=VERTEX_POINT('',#745);
#747=EDGE_CURVE('E786',#746,#738,#744,.T.);
#748=ORIENTED_EDGE('',*,*,#747,.F.);
#749=DIRECTION('',(0.,0.,-1.));
#750=VECTOR('',#749,1.);
#751=CARTESIAN_POINT('',(6.4,12.5,4.4));
#752=LINE('',#751,#750);
#753=EDGE_CURVE('E789',#263,#746,#752,.T.);
#754=ORIENTED_EDGE('',*,*,#753,.F.);
#755=ORIENTED_EDGE('',*,*,#264,.F.);
#756=DIRECTION('',(0.,0.,1.));
#757=VECTOR('',#756,1.);
#758=CARTESIAN_POINT('',(7.6,12.5,4.4));
#759=LINE('',#758,#757);
#760=CARTESIAN_POINT('',(7.6,12.5,3.6));
#761=VERTEX_POINT('',#760);
#762=EDGE_CURVE('E805',#761,#259,#759,.T.);
#763=ORIENTED_EDGE('',*,*,#762,.F.);
#764=DIRECTION('',(-1.,0.,0.));
#765=VECTOR('',#764,1.);
#766=CARTESIAN_POINT('',(7.6,12.5,3.6));
#767=LINE('',#766,#765);
#768=CARTESIAN_POINT('',(8.4,12.5,3.6));
#769=VERTEX_POINT('',#768);
#770=EDGE_CURVE('E808',#769,#761,#767,.T.);
#771=ORIENTED_EDGE('',*,*,#770,.F.);
#772=DIRECTION('',(0.,0.,-1.));
#773=VECTOR('',#772,1.);
#774=CARTESIAN_POINT('',(8.4,12.5,4.4));
#775=LINE('',#774,#773);
#776=EDGE_CURVE('E811',#236,#769,#775,.T.);
#777=ORIENTED_EDGE('',*,*,#776,.F.);
#778=ORIENTED_EDGE('',*,*,#237,.F.);
#779=DIRECTION('',(0.,0.,1.));
#780=VECTOR('',#779,1.);
#781=CARTESIAN_POINT('',(9.6,12.5,4.4));
#782=LINE('',#781,#780);
#783=CARTESIAN_POINT('',(9.6,12.5,3.6));
#784=VERTEX_POINT('',#783);
#785=EDGE_CURVE('E827',#784,#232,#782,.T.);
#786=ORIENTED_EDGE('',*,*,#785,.F.);
#787=DIRECTION('',(-1.,0.,0.));
#788=VECTOR('',#787,1.);
#789=CARTESIAN_POINT('',(9.6,12.5,3.6));
#790=LINE('',#789,#788);
#791=CARTESIAN_POINT('',(10.4,12.5,3.6));
#792=VERTEX_POINT('',#791);
#793=EDGE_CURVE('E830',#792,#784,#790,.T.);
#794=ORIENTED_EDGE('',*,*,#793,.F.);
#795=DIRECTION('',(0.,0.,-1.));
#796=VECTOR('',#795,1.);
#797=CARTESIAN_POINT('',(10.4,12.5,4.4));
#798=LINE('',#797,#796);
#799=EDGE_CURVE('E833',#209,#792,#798,.T.);
#800=ORIENTED_EDGE('',*,*,#799,.F.);
#801=ORIENTED_EDGE('',*,*,#210,.F.);
#802=DIRECTION('',(0.,0.,1.));
#803=VECTOR('',#802,1.);
#804=CARTESIAN_POINT('',(11.6,12.5,4.4));
#805=LINE('',#804,#803);
#806=CARTESIAN_POINT('',(11.6,12.5,3.6));
#807=VERTEX_POINT('',#806);
#808=EDGE_CURVE('E849',#807,#205,#805,.T.);
#809=ORIENTED_EDGE('',*,*,#808,.F.);
#810=DIRECTION('',(-1.,0.,0.));
#811=VECTOR('',#810,1.);
#812=CARTESIAN_POINT('',(11.6,12.5,3.6));
#813=LINE('',#812,#811);
#814=CARTESIAN_POINT('',(12.4,12.5,3.6));
#815=VERTEX_POINT('',#814);
#816=EDGE_CURVE('E852',#815,#807,#813,.T.);
#817=ORIENTED_EDGE('',*,*,#816,.F.);
#818=DIRECTION('',(0.,0.,-1.));
#819=VECTOR('',#818,1.);
#820=CARTESIAN_POINT('',(12.4,12.5,4.4));
#821=LINE('',#820,#819);
#822=EDGE_CURVE('E855',#182,#815,#821,.T.);
#823=ORIENTED_EDGE('',*,*,#822,.F.);
#824=ORIENTED_EDGE('',*,*,#183,.F.);
#825=DIRECTION('',(0.,0.,1.));
#826=VECTOR('',#825,1.);
#827=CARTESIAN_POINT('',(13.6,12.5,4.4));
#828=LINE('',#827,#826);
#829=CARTESIAN_POINT('',(13.6,12.5,3.6));
#830=VERTEX_POINT('',#829);
#831=EDGE_CURVE('E871',#830,#178,#828,.T.);
#832=ORIENTED_EDGE('',*,*,#831,.F.);
#833=DIRECTION('',(-1.,0.,0.));
#834=VECTOR('',#833,1.);
#835=CARTESIAN_POINT('',(13.6,12.5,3.6));
#836=LINE('',#835,#834);
#837=CARTESIAN_POINT('',(14.4,12.5,3.6));
#838=VERTEX_POINT('',#837);
#839=EDGE_CURVE('E874',#838,#830,#836,.T.);
#840=ORIENTED_EDGE('',*,*,#839,.F.);
#841=DIRECTION('',(0.,0.,-1.));
#842=VECTOR('',#841,1.);
#843=CARTESIAN_POINT('',(14.4,12.5,4.4));
#844=LINE('',#843,#842);
#845=EDGE_CURVE('E877',#155,#838,#844,.T.);
#846=ORIENTED_EDGE('',*,*,#845,.F.);
#847=ORIENTED_EDGE('',*,*,#156,.F.);
#848=DIRECTION('',(0.,0.,1.));
#849=VECTOR('',#848,1.);
#850=CARTESIAN_POINT('',(15.6,12.5,4.4));
#851=LINE('',#850,#849);
#852=CARTESIAN_POINT('',(15.6,12.5,3.6));
#853=VERTEX_POINT('',#852);
#854=EDGE_CURVE('E893',#853,#151,#851,.T.);
#855=ORIENTED_EDGE('',*,*,#854,.F.);
#856=DIRECTION('',(-1.,0.,0.));
#857=VECTOR('',#856,1.);
#858=CARTESIAN_POINT('',(15.6,12.5,3.6));
#859=LINE('',#858,#857);
#860=CARTESIAN_POINT('',(16.4,12.5,3.6));
#861=VERTEX_POINT('',#860);
#862=EDGE_CURVE('E896',#861,#853,#859,.T.);
#863=ORIENTED_EDGE('',*,*,#862,.F.);
#864=DIRECTION('',(0.,0.,-1.));
#865=VECTOR('',#864,1.);
#866=CARTESIAN_POINT('',(16.4,12.5,4.4));
#867=LINE('',#866,#865);
#868=EDGE_CURVE('E899',#128,#861,#867,.T.);
#869=ORIENTED_EDGE('',*,*,#868,.F.);
#870=ORIENTED_EDGE('',*,*,#129,.F.);
#871=DIRECTION('',(0.,0.,1.));
#872=VECTOR('',#871,1.);
#873=CARTESIAN_POINT('',(17.6,12.5,4.4));
#874=LINE('',#873,#872);
#875=CARTESIAN_POINT('',(17.6,12.5,3.6));
#876=VERTEX_POINT('',#875);
#877=EDGE_CURVE('E915',#876,#124,#874,.T.);
#878=ORIENTED_EDGE('',*,*,#877,.F.);
#879=DIRECTION('',(-1.,0.,0.));
#880=VECTOR('',#879,1.);
#881=CARTESIAN_POINT('',(17.6,12.5,3.6));
#882=LINE('',#881,#880);
#883=CARTESIAN_POINT('',(18.4,12.5,3.6));
#884=VERTEX_POINT('',#883);
#885=EDGE_CURVE('E918',#884,#876,#882,.T.);
#886=ORIENTED_EDGE('',*,*,#885,.F.);
#887=DIRECTION('',(0.,0.,-1.));
#888=VECTOR('',#887,1.);
#889=CARTESIAN_POINT('',(18.4,12.5,4.4));
#890=LINE('',#889,#888);
#891=EDGE_CURVE('E921',#101,#884,#890,.T.);
#892=ORIENTED_EDGE('',*,*,#891,.F.);
#893=ORIENTED_EDGE('',*,*,#102,.F.);
#894=DIRECTION('',(0.,0.,1.));
#895=VECTOR('',#894,1.);
#896=CARTESIAN_POINT('',(19.6,12.5,4.4));
#897=LINE('',#896,#895);
#898=CARTESIAN_POINT('',(19.6,12.5,3.6));
#899=VERTEX_POINT('',#898);
#900=EDGE_CURVE('E935',#899,#97,#897,.T.);
#901=ORIENTED_EDGE('',*,*,#900,.F.);
#902=DIRECTION('',(-1.,0.,0.));
#903=VECTOR('',#902,1.);
#904=CARTESIAN_POINT('',(19.6,12.5,3.6));
#905=LINE('',#904,#903);
#906=CARTESIAN_POINT('',(20.4,12.5,3.6));
#907=VERTEX_POINT('',#906);
#908=EDGE_CURVE('E938',#907,#899,#905,.T.);
#909=ORIENTED_EDGE('',*,*,#908,.F.);
#910=DIRECTION('',(0.,0.,-1.));
#911=VECTOR('',#910,1.);
#912=CARTESIAN_POINT('',(20.4,12.5,4.4));
#913=LINE('',#912,#911);
#914=EDGE_CURVE('E941',#74,#907,#913,.T.);
#915=ORIENTED_EDGE('',*,*,#914,.F.);
#916=ORIENTED_EDGE('',*,*,#75,.F.);
#917=DIRECTION('',(0.,0.,1.));
#918=VECTOR('',#917,1.);
#919=CARTESIAN_POINT('',(21.6,12.5,4.4));
#920=LINE('',#919,#918);
#921=CARTESIAN_POINT('',(21.6,12.5,3.6));
#922=VERTEX_POINT('',#921);
#923=EDGE_CURVE('E499',#922,#70,#920,.T.);
#924=ORIENTED_EDGE('',*,*,#923,.F.);
#925=DIRECTION('',(-1.,0.,0.));
#926=VECTOR('',#925,1.);
#927=CARTESIAN_POINT('',(21.6,12.5,3.6));
#928=LINE('',#927,#926);
#929=CARTESIAN_POINT('',(22.4,12.5,3.6));
#930=VERTEX_POINT('',#929);
#931=EDGE_CURVE('E956',#930,#922,#928,.T.);
#932=ORIENTED_EDGE('',*,*,#931,.F.);
#933=DIRECTION('',(0.,0.,-1.));
#934=VECTOR('',#933,1.);
#935=CARTESIAN_POINT('',(22.4,12.5,4.4));
#936=LINE('',#935,#934);
#937=EDGE_CURVE('E959',#31,#930,#936,.T.);
#938=ORIENTED_EDGE('',*,*,#937,.F.);
#939=ORIENTED_EDGE('',*,*,#32,.F.);
#940=DIRECTION('',(0.,0.,1.));
#941=VECTOR('',#940,1.);
#942=CARTESIAN_POINT('',(23.6,12.5,4.4));
#943=LINE('',#942,#941);
#944=CARTESIAN_POINT('',(23.6,12.5,3.6));
#945=VERTEX_POINT('',#944);
#946=EDGE_CURVE('E628',#945,#29,#943,.T.);
#947=ORIENTED_EDGE('',*,*,#946,.F.);
#948=DIRECTION('',(-1.,0.,0.));
#949=VECTOR('',#948,1.);
#950=CARTESIAN_POINT('',(23.6,12.5,3.6));
#951=LINE('',#950,#949);
#952=CARTESIAN_POINT('',(24.4,12.5,3.6));
#953=VERTEX_POINT('',#952);
#954=EDGE_CURVE('E631',#953,#945,#951,.T.);
#955=ORIENTED_EDGE('',*,*,#954,.F.);
#956=DIRECTION('',(0.,0.,-1.));
#957=VECTOR('',#956,1.);
#958=CARTESIAN_POINT('',(24.4,12.5,4.4));
#959=LINE('',#958,#957);
#960=EDGE_CURVE('E634',#440,#953,#959,.T.);
#961=ORIENTED_EDGE('',*,*,#960,.F.);
#962=ORIENTED_EDGE('',*,*,#441,.F.);
#963=ORIENTED_EDGE('',*,*,#563,.T.);
#964=DIRECTION('',(-0.86602540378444,0.,-0.499999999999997));
#965=VECTOR('',#964,1.);
#966=CARTESIAN_POINT('',(25.,12.5,2.3094010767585));
#967=LINE('',#966,#965);
#968=EDGE_CURVE('E552',#556,#492,#967,.T.);
#969=ORIENTED_EDGE('',*,*,#968,.T.);
#970=EDGE_LOOP('',(#574,#582,#590,#594,#602,#610,#616,#617,#625,#633,#639,#640,#648,#656,#662,
#663,#671,#679,#685,#686,#694,#702,#708,#709,#717,#725,#731,#732,#740,#748,#754,#755,#763,#771,
#777,#778,#786,#794,#800,#801,#809,#817,#823,#824,#832,#840,#846,#847,#855,#863,#869,#870,#878,
#886,#892,#893,#901,#909,#915,#916,#924,#932,#938,#939,#947,#955,#961,#962,#963,#969));
#971=FACE_BOUND('',#970,.T.);
#972=ADVANCED_FACE('F973',(#971),#573,.F.);
#973=CARTESIAN_POINT('',(-25.,-12.5,4.));
#974=DIRECTION('',(1.,0.,0.));
#975=DIRECTION('',(0.,0.,-1.));
#976=AXIS2_PLACEMENT_3D('',#973,#974,#975);
#977=PLANE('',#976);
#978=ORIENTED_EDGE('',*,*,#589,.T.);
#979=DIRECTION('',(0.,-1.,0.));
#980=VECTOR('',#979,1.);
#981=CARTESIAN_POINT('',(-25.,-12.5,0.57735026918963));
#982=LINE('',#981,#980);
#983=CARTESIAN_POINT('',(-25.,-12.5,0.57735026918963));
#984=VERTEX_POINT('',#983);
#985=EDGE_CURVE('E559',#580,#984,#982,.T.);
#986=ORIENTED_EDGE('',*,*,#985,.T.);
#987=DIRECTION('',(0.,0.,-1.));
#988=VECTOR('',#987,1.);
#989=CARTESIAN_POINT('',(-25.,-12.5,4.));
#990=LINE('',#989,#988);
#991=CARTESIAN_POINT('',(-25.,-12.5,4.));
#992=VERTEX_POINT('',#991);
#993=EDGE_CURVE('E541',#992,#984,#990,.T.);
#994=ORIENTED_EDGE('',*,*,#993,.F.);
#995=DIRECTION('',(0.,-1.,0.));
#996=VECTOR('',#995,1.);
#997=CARTESIAN_POINT('',(-25.,-12.5,4.));
#998=LINE('',#997,#996);
#999=EDGE_CURVE('E531',#588,#992,#998,.T.);
#1000=ORIENTED_EDGE('',*,*,#999,.F.);
#1001=EDGE_LOOP('',(#978,#986,#994,#1000));
#1002=FACE_BOUND('',#1001,.T.);
#1003=ADVANCED_FACE('F565',(#1002),#977,.F.);
#1004=CARTESIAN_POINT('',(-25.,-12.5,4.));
#1005=DIRECTION('',(0.,1.,0.));
#1006=DIRECTION('',(0.,0.,1.));
#1007=AXIS2_PLACEMENT_3D('',#1004,#1005,#1006);
#1008=PLANE('',#1007);
#1009=ORIENTED_EDGE('',*,*,#993,.T.);
#1010=DIRECTION('',(0.866025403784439,0.,-0.5));
#1011=VECTOR('',#1010,1.);
#1012=CARTESIAN_POINT('',(-25.,-12.5,0.57735026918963));
#1013=LINE('',#1012,#1011);
#1014=EDGE_CURVE('E56',#984,#474,#1013,.T.);
#1015=ORIENTED_EDGE('',*,*,#1014,.T.);
#1016=ORIENTED_EDGE('',*,*,#477,.T.);
#1017=DIRECTION('',(0.86602540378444,0.,0.499999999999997));
#1018=VECTOR('',#1017,1.);
#1019=CARTESIAN_POINT('',(25.,-12.5,2.3094010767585));
#1020=LINE('',#1019,#1018);
#1021=EDGE_CURVE('E557',#476,#548,#1020,.T.);
#1022=ORIENTED_EDGE('',*,*,#1021,.T.);
#1023=ORIENTED_EDGE('',*,*,#549,.F.);
#1024=ORIENTED_EDGE('',*,*,#453,.F.);
#1025=DIRECTION('',(0.,0.,1.));
#1026=VECTOR('',#1025,1.);
#1027=CARTESIAN_POINT('',(24.4,-12.5,4.4));
#1028=LINE('',#1027,#1026);
#1029=CARTESIAN_POINT('',(24.4,-12.5,3.6));
#1030=VERTEX_POINT('',#1029);
#1031=EDGE_CURVE('E637',#1030,#448,#1028,.T.);
#1032=ORIENTED_EDGE('',*,*,#1031,.F.);
#1033=DIRECTION('',(1.,0.,0.));
#1034=VECTOR('',#1033,1.);
#1035=CARTESIAN_POINT('',(23.6,-12.5,3.6));
#1036=LINE('',#1035,#1034);
#1037=CARTESIAN_POINT('',(23.6,-12.5,3.6));
#1038=VERTEX_POINT('',#1037);
#1039=EDGE_CURVE('E616',#1038,#1030,#1036,.T.);
#1040=ORIENTED_EDGE('',*,*,#1039,.F.);
#1041=DIRECTION('',(0.,0.,-1.));
#1042=VECTOR('',#1041,1.);
#1043=CARTESIAN_POINT('',(23.6,-12.5,4.4));
#1044=LINE('',#1043,#1042);
#1045=EDGE_CURVE('E639',#47,#1038,#1044,.T.);
#1046=ORIENTED_EDGE('',*,*,#1045,.F.);
#1047=ORIENTED_EDGE('',*,*,#48,.F.);
#1048=DIRECTION('',(0.,0.,1.));
#1049=VECTOR('',#1048,1.);
#1050=CARTESIAN_POINT('',(22.4,-12.5,4.4));
#1051=LINE('',#1050,#1049);
#1052=CARTESIAN_POINT('',(22.4,-12.5,3.6));
#1053=VERTEX_POINT('',#1052);
#1054=EDGE_CURVE('E514',#1053,#39,#1051,.T.);
#1055=ORIENTED_EDGE('',*,*,#1054,.F.);
#1056=DIRECTION('',(1.,0.,0.));
#1057=VECTOR('',#1056,1.);
#1058=CARTESIAN_POINT('',(21.6,-12.5,3.6));
#1059=LINE('',#1058,#1057);
#1060=CARTESIAN_POINT('',(21.6,-12.5,3.6));
#1061=VERTEX_POINT('',#1060);
#1062=EDGE_CURVE('E513',#1061,#1053,#1059,.T.);
#1063=ORIENTED_EDGE('',*,*,#1062,.F.);
#1064=DIRECTION('',(0.,0.,-1.));
#1065=VECTOR('',#1064,1.);
#1066=CARTESIAN_POINT('',(21.6,-12.5,4.4));
#1067=LINE('',#1066,#1065);
#1068=EDGE_CURVE('E496',#62,#1061,#1067,.T.);
#1069=ORIENTED_EDGE('',*,*,#1068,.F.);
#1070=ORIENTED_EDGE('',*,*,#63,.F.);
#1071=DIRECTION('',(0.,0.,1.));
#1072=VECTOR('',#1071,1.);
#1073=CARTESIAN_POINT('',(20.4,-12.5,4.4));
#1074=LINE('',#1073,#1072);
#1075=CARTESIAN_POINT('',(20.4,-12.5,3.6));
#1076=VERTEX_POINT('',#1075);
#1077=EDGE_CURVE('E944',#1076,#60,#1074,.T.);
#1078=ORIENTED_EDGE('',*,*,#1077,.F.);
#1079=DIRECTION('',(1.,0.,0.));
#1080=VECTOR('',#1079,1.);
#1081=CARTESIAN_POINT('',(19.6,-12.5,3.6));
#1082=LINE('',#1081,#1080);
#1083=CARTESIAN_POINT('',(19.6,-12.5,3.6));
#1084=VERTEX_POINT('',#1083);
#1085=EDGE_CURVE('E505',#1084,#1076,#1082,.T.);
#1086=ORIENTED_EDGE('',*,*,#1085,.F.);
#1087=DIRECTION('',(0.,0.,-1.));
#1088=VECTOR('',#1087,1.);
#1089=CARTESIAN_POINT('',(19.6,-12.5,4.4));
#1090=LINE('',#1089,#1088);
#1091=EDGE_CURVE('E946',#89,#1084,#1090,.T.);
#1092=ORIENTED_EDGE('',*,*,#1091,.F.);
#1093=ORIENTED_EDGE('',*,*,#90,.F.);
#1094=DIRECTION('',(0.,0.,1.));
#1095=VECTOR('',#1094,1.);
#1096=CARTESIAN_POINT('',(18.4,-12.5,4.4));
#1097=LINE('',#1096,#1095);
#1098=CARTESIAN_POINT('',(18.4,-12.5,3.6));
#1099=VERTEX_POINT('',#1098);
#1100=EDGE_CURVE('E924',#1099,#87,#1097,.T.);
#1101=ORIENTED_EDGE('',*,*,#1100,.F.);
#1102=DIRECTION('',(1.,0.,0.));
#1103=VECTOR('',#1102,1.);
#1104=CARTESIAN_POINT('',(17.6,-12.5,3.6));
#1105=LINE('',#1104,#1103);
#1106=CARTESIAN_POINT('',(17.6,-12.5,3.6));
#1107=VERTEX_POINT('',#1106);
#1108=EDGE_CURVE('E909',#1107,#1099,#1105,.T.);
#1109=ORIENTED_EDGE('',*,*,#1108,.F.);
#1110=DIRECTION('',(0.,0.,-1.));
#1111=VECTOR('',#1110,1.);
#1112=CARTESIAN_POINT('',(17.6,-12.5,4.4));
#1113=LINE('',#1112,#1111);
#1114=EDGE_CURVE('E926',#116,#1107,#1113,.T.);
#1115=ORIENTED_EDGE('',*,*,#1114,.F.);
#1116=ORIENTED_EDGE('',*,*,#117,.F.);
#1117=DIRECTION('',(0.,0.,1.));
#1118=VECTOR('',#1117,1.);
#1119=CARTESIAN_POINT('',(16.4,-12.5,4.4));
#1120=LINE('',#1119,#1118);
#1121=CARTESIAN_POINT('',(16.4,-12.5,3.6));
#1122=VERTEX_POINT('',#1121);
#1123=EDGE_CURVE('E902',#1122,#114,#1120,.T.);
#1124=ORIENTED_EDGE('',*,*,#1123,.F.);
#1125=DIRECTION('',(1.,0.,0.));
#1126=VECTOR('',#1125,1.);
#1127=CARTESIAN_POINT('',(15.6,-12.5,3.6));
#1128=LINE('',#1127,#1126);
#1129=CARTESIAN_POINT('',(15.6,-12.5,3.6));
#1130=VERTEX_POINT('',#1129);
#1131=EDGE_CURVE('E887',#1130,#1122,#1128,.T.);
#1132=ORIENTED_EDGE('',*,*,#1131,.F.);
#1133=DIRECTION('',(0.,0.,-1.));
#1134=VECTOR('',#1133,1.);
#1135=CARTESIAN_POINT('',(15.6,-12.5,4.4));
#1136=LINE('',#1135,#1134);
#1137=EDGE_CURVE('E904',#143,#1130,#1136,.T.);
#1138=ORIENTED_EDGE('',*,*,#1137,.F.);
#1139=ORIENTED_EDGE('',*,*,#144,.F.);
#1140=DIRECTION('',(0.,0.,1.));
#1141=VECTOR('',#1140,1.);
#1142=CARTESIAN_POINT('',(14.4,-12.5,4.4));
#1143=LINE('',#1142,#1141);
#1144=CARTESIAN_POINT('',(14.4,-12.5,3.6));
#1145=VERTEX_POINT('',#1144);
#1146=EDGE_CURVE('E880',#1145,#141,#1143,.T.);
#1147=ORIENTED_EDGE('',*,*,#1146,.F.);
#1148=DIRECTION('',(1.,0.,0.));
#1149=VECTOR('',#1148,1.);
#1150=CARTESIAN_POINT('',(13.6,-12.5,3.6));
#1151=LINE('',#1150,#1149);
#1152=CARTESIAN_POINT('',(13.6,-12.5,3.6));
#1153=VERTEX_POINT('',#1152);
#1154=EDGE_CURVE('E865',#1153,#1145,#1151,.T.);
#1155=ORIENTED_EDGE('',*,*,#1154,.F.);
#1156=DIRECTION('',(0.,0.,-1.));
#1157=VECTOR('',#1156,1.);
#1158=CARTESIAN_POINT('',(13.6,-12.5,4.4));
#1159=LINE('',#1158,#1157);
#1160=EDGE_CURVE('E882',#170,#1153,#1159,.T.);
#1161=ORIENTED_EDGE('',*,*,#1160,.F.);
#1162=ORIENTED_EDGE('',*,*,#171,.F.);
#1163=DIRECTION('',(0.,0.,1.));
#1164=VECTOR('',#1163,1.);
#1165=CARTESIAN_POINT('',(12.4,-12.5,4.4));
#1166=LINE('',#1165,#1164);
#1167=CARTESIAN_POINT('',(12.4,-12.5,3.6));
#1168=VERTEX_POINT('',#1167);
#1169=EDGE_CURVE('E858',#1168,#168,#1166,.T.);
#1170=ORIENTED_EDGE('',*,*,#1169,.F.);
#1171=DIRECTION('',(1.,0.,0.));
#1172=VECTOR('',#1171,1.);
#1173=CARTESIAN_POINT('',(11.6,-12.5,3.6));
#1174=LINE('',#1173,#1172);
#1175=CARTESIAN_POINT('',(11.6,-12.5,3.6));
#1176=VERTEX_POINT('',#1175);
#1177=EDGE_CURVE('E843',#1176,#1168,#1174,.T.);
#1178=ORIENTED_EDGE('',*,*,#1177,.F.);
#1179=DIRECTION('',(0.,0.,-1.));
#1180=VECTOR('',#1179,1.);
#1181=CARTESIAN_POINT('',(11.6,-12.5,4.4));
#1182=LINE('',#1181,#1180);
#1183=EDGE_CURVE('E860',#197,#1176,#1182,.T.);
#1184=ORIENTED_EDGE('',*,*,#1183,.F.);
#1185=ORIENTED_EDGE('',*,*,#198,.F.);
#1186=DIRECTION('',(0.,0.,1.));
#1187=VECTOR('',#1186,1.);
#1188=CARTESIAN_POINT('',(10.4,-12.5,4.4));
#1189=LINE('',#1188,#1187);
#1190=CARTESIAN_POINT('',(10.4,-12.5,3.6));
#1191=VERTEX_POINT('',#1190);
#1192=EDGE_CURVE('E836',#1191,#195,#1189,.T.);
#1193=ORIENTED_EDGE('',*,*,#1192,.F.);
#1194=DIRECTION('',(1.,0.,0.));
#1195=VECTOR('',#1194,1.);
#1196=CARTESIAN_POINT('',(9.6,-12.5,3.6));
#1197=LINE('',#1196,#1195);
#1198=CARTESIAN_POINT('',(9.6,-12.5,3.6));
#1199=VERTEX_POINT('',#1198);
#1200=EDGE_CURVE('E821',#1199,#1191,#1197,.T.);
#1201=ORIENTED_EDGE('',*,*,#1200,.F.);
#1202=DIRECTION('',(0.,0.,-1.));
#1203=VECTOR('',#1202,1.);
#1204=CARTESIAN_POINT('',(9.6,-12.5,4.4));
#1205=LINE('',#1204,#1203);
#1206=EDGE_CURVE('E838',#224,#1199,#1205,.T.);
#1207=ORIENTED_EDGE('',*,*,#1206,.F.);
#1208=ORIENTED_EDGE('',*,*,#225,.F.);
#1209=DIRECTION('',(0.,0.,1.));
#1210=VECTOR('',#1209,1.);
#1211=CARTESIAN_POINT('',(8.4,-12.5,4.4));
#1212=LINE('',#1211,#1210);
#1213=CARTESIAN_POINT('',(8.4,-12.5,3.6));
#1214=VERTEX_POINT('',#1213);
#1215=EDGE_CURVE('E814',#1214,#222,#1212,.T.);
#1216=ORIENTED_EDGE('',*,*,#1215,.F.);
#1217=DIRECTION('',(1.,0.,0.));
#1218=VECTOR('',#1217,1.);
#1219=CARTESIAN_POINT('',(7.6,-12.5,3.6));
#1220=LINE('',#1219,#1218);
#1221=CARTESIAN_POINT('',(7.6,-12.5,3.6));
#1222=VERTEX_POINT('',#1221);
#1223=EDGE_CURVE('E799',#1222,#1214,#1220,.T.);
#1224=ORIENTED_EDGE('',*,*,#1223,.F.);
#1225=DIRECTION('',(0.,0.,-1.));
#1226=VECTOR('',#1225,1.);
#1227=CARTESIAN_POINT('',(7.6,-12.5,4.4));
#1228=LINE('',#1227,#1226);
#1229=EDGE_CURVE('E816',#251,#1222,#1228,.T.);
#1230=ORIENTED_EDGE('',*,*,#1229,.F.);
#1231=ORIENTED_EDGE('',*,*,#252,.F.);
#1232=DIRECTION('',(0.,0.,1.));
#1233=VECTOR('',#1232,1.);
#1234=CARTESIAN_POINT('',(6.4,-12.5,4.4));
#1235=LINE('',#1234,#1233);
#1236=CARTESIAN_POINT('',(6.4,-12.5,3.6));
#1237=VERTEX_POINT('',#1236);
#1238=EDGE_CURVE('E792',#1237,#249,#1235,.T.);
#1239=ORIENTED_EDGE('',*,*,#1238,.F.);
#1240=DIRECTION('',(1.,0.,0.));
#1241=VECTOR('',#1240,1.);
#1242=CARTESIAN_POINT('',(5.6,-12.5,3.6));
#1243=LINE('',#1242,#1241);
#1244=CARTESIAN_POINT('',(5.6,-12.5,3.6));
#1245=VERTEX_POINT('',#1244);
#1246=EDGE_CURVE('E777',#1245,#1237,#1243,.T.);
#1247=ORIENTED_EDGE('',*,*,#1246,.F.);
#1248=DIRECTION('',(0.,0.,-1.));
#1249=VECTOR('',#1248,1.);
#1250=CARTESIAN_POINT('',(5.6,-12.5,4.4));
#1251=LINE('',#1250,#1249);
#1252=EDGE_CURVE('E794',#278,#1245,#1251,.T.);
#1253=ORIENTED_EDGE('',*,*,#1252,.F.);
#1254=ORIENTED_EDGE('',*,*,#279,.F.);
#1255=DIRECTION('',(0.,0.,1.));
#1256=VECTOR('',#1255,1.);
#1257=CARTESIAN_POINT('',(4.4,-12.5,4.4));
#1258=LINE('',#1257,#1256);
#1259=CARTESIAN_POINT('',(4.4,-12.5,3.6));
#1260=VERTEX_POINT('',#1259);
#1261=EDGE_CURVE('E770',#1260,#276,#1258,.T.);
#1262=ORIENTED_EDGE('',*,*,#1261,.F.);
#1263=DIRECTION('',(1.,0.,0.));
#1264=VECTOR('',#1263,1.);
#1265=CARTESIAN_POINT('',(3.6,-12.5,3.6));
#1266=LINE('',#1265,#1264);
#1267=CARTESIAN_POINT('',(3.6,-12.5,3.6));
#1268=VERTEX_POINT('',#1267);
#1269=EDGE_CURVE('E755',#1268,#1260,#1266,.T.);
#1270=ORIENTED_EDGE('',*,*,#1269,.F.);
#1271=DIRECTION('',(0.,0.,-1.));
#1272=VECTOR('',#1271,1.);
#1273=CARTESIAN_POINT('',(3.6,-12.5,4.4));
#1274=LINE('',#1273,#1272);
#1275=EDGE_CURVE('E772',#305,#1268,#1274,.T.);
#1276=ORIENTED_EDGE('',*,*,#1275,.F.);
#1277=ORIENTED_EDGE('',*,*,#306,.F.);
#1278=DIRECTION('',(0.,0.,1.));
#1279=VECTOR('',#1278,1.);
#1280=CARTESIAN_POINT('',(2.4,-12.5,4.4));
#1281=LINE('',#1280,#1279);
#1282=CARTESIAN_POINT('',(2.4,-12.5,3.6));
#1283=VERTEX_POINT('',#1282);
#1284=EDGE_CURVE('E748',#1283,#303,#1281,.T.);
#1285=ORIENTED_EDGE('',*,*,#1284,.F.);
#1286=DIRECTION('',(1.,0.,0.));
#1287=VECTOR('',#1286,1.);
#1288=CARTESIAN_POINT('',(1.6,-12.5,3.6));
#1289=LINE('',#1288,#1287);
#1290=CARTESIAN_POINT('',(1.6,-12.5,3.6));
#1291=VERTEX_POINT('',#1290);
#1292=EDGE_CURVE('E733',#1291,#1283,#1289,.T.);
#1293=ORIENTED_EDGE('',*,*,#1292,.F.);
#1294=DIRECTION('',(0.,0.,-1.));
#1295=VECTOR('',#1294,1.);
#1296=CARTESIAN_POINT('',(1.6,-12.5,4.4));
#1297=LINE('',#1296,#1295);
#1298=EDGE_CURVE('E750',#332,#1291,#1297,.T.);
#1299=ORIENTED_EDGE('',*,*,#1298,.F.);
#1300=ORIENTED_EDGE('',*,*,#333,.F.);
#1301=DIRECTION('',(0.,0.,1.));
#1302=VECTOR('',#1301,1.);
#1303=CARTESIAN_POINT('',(0.399999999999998,-12.5,4.4));
#1304=LINE('',#1303,#1302);
#1305=CARTESIAN_POINT('',(0.399999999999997,-12.5,3.6));
#1306=VERTEX_POINT('',#1305);
#1307=EDGE_CURVE('E726',#1306,#330,#1304,.T.);
#1308=ORIENTED_EDGE('',*,*,#1307,.F.);
#1309=DIRECTION('',(1.,0.,0.));
#1310=VECTOR('',#1309,1.);
#1311=CARTESIAN_POINT('',(-0.400000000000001,-12.5,3.6));
#1312=LINE('',#1311,#1310);
#1313=CARTESIAN_POINT('',(-0.400000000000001,-12.5,3.6));
#1314=VERTEX_POINT('',#1313);
#1315=EDGE_CURVE('E711',#1314,#1306,#1312,.T.);
#1316=ORIENTED_EDGE('',*,*,#1315,.F.);
#1317=DIRECTION('',(0.,0.,-1.));
#1318=VECTOR('',#1317,1.);
#1319=CARTESIAN_POINT('',(-0.400000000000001,-12.5,4.4));
#1320=LINE('',#1319,#1318);
#1321=EDGE_CURVE('E728',#359,#1314,#1320,.T.);
#1322=ORIENTED_EDGE('',*,*,#1321,.F.);
#1323=ORIENTED_EDGE('',*,*,#360,.F.);
#1324=DIRECTION('',(0.,0.,1.));
#1325=VECTOR('',#1324,1.);
#1326=CARTESIAN_POINT('',(-1.6,-12.5,4.4));
#1327=LINE('',#1326,#1325);
#1328=CARTESIAN_POINT('',(-1.6,-12.5,3.6));
#1329=VERTEX_POINT('',#1328);
#1330=EDGE_CURVE('E704',#1329,#357,#1327,.T.);
#1331=ORIENTED_EDGE('',*,*,#1330,.F.);
#1332=DIRECTION('',(1.,0.,0.));
#1333=VECTOR('',#1332,1.);
#1334=CARTESIAN_POINT('',(-2.4,-12.5,3.6));
#1335=LINE('',#1334,#1333);
#1336=CARTESIAN_POINT('',(-2.4,-12.5,3.6));
#1337=VERTEX_POINT('',#1336);
#1338=EDGE_CURVE('E689',#1337,#1329,#1335,.T.);
#1339=ORIENTED_EDGE('',*,*,#1338,.F.);
#1340=DIRECTION('',(0.,0.,-1.));
#1341=VECTOR('',#1340,1.);
#1342=CARTESIAN_POINT('',(-2.4,-12.5,4.4));
#1343=LINE('',#1342,#1341);
#1344=EDGE_CURVE('E706',#386,#1337,#1343,.T.);
#1345=ORIENTED_EDGE('',*,*,#1344,.F.);
#1346=ORIENTED_EDGE('',*,*,#387,.F.);
#1347=DIRECTION('',(0.,0.,1.));
#1348=VECTOR('',#1347,1.);
#1349=CARTESIAN_POINT('',(-3.6,-12.5,4.4));
#1350=LINE('',#1349,#1348);
#1351=CARTESIAN_POINT('',(-3.6,-12.5,3.6));
#1352=VERTEX_POINT('',#1351);
#1353=EDGE_CURVE('E682',#1352,#384,#1350,.T.);
#1354=ORIENTED_EDGE('',*,*,#1353,.F.);
#1355=DIRECTION('',(1.,0.,0.));
#1356=VECTOR('',#1355,1.);
#1357=CARTESIAN_POINT('',(-4.4,-12.5,3.6));
#1358=LINE('',#1357,#1356);
#1359=CARTESIAN_POINT('',(-4.4,-12.5,3.6));
#1360=VERTEX_POINT('',#1359);
#1361=EDGE_CURVE('E667',#1360,#1352,#1358,.T.);
#1362=ORIENTED_EDGE('',*,*,#1361,.F.);
#1363=DIRECTION('',(0.,0.,-1.));
#1364=VECTOR('',#1363,1.);
#1365=CARTESIAN_POINT('',(-4.4,-12.5,4.4));
#1366=LINE('',#1365,#1364);
#1367=EDGE_CURVE('E684',#413,#1360,#1366,.T.);
#1368=ORIENTED_EDGE('',*,*,#1367,.F.);
#1369=ORIENTED_EDGE('',*,*,#414,.F.);
#1370=DIRECTION('',(0.,0.,1.));
#1371=VECTOR('',#1370,1.);
#1372=CARTESIAN_POINT('',(-5.6,-12.5,4.4));
#1373=LINE('',#1372,#1371);
#1374=CARTESIAN_POINT('',(-5.6,-12.5,3.6));
#1375=VERTEX_POINT('',#1374);
#1376=EDGE_CURVE('E661',#1375,#411,#1373,.T.);
#1377=ORIENTED_EDGE('',*,*,#1376,.F.);
#1378=DIRECTION('',(1.,0.,0.));
#1379=VECTOR('',#1378,1.);
#1380=CARTESIAN_POINT('',(-6.4,-12.5,3.6));
#1381=LINE('',#1380,#1379);
#1382=CARTESIAN_POINT('',(-6.4,-12.5,3.6));
#1383=VERTEX_POINT('',#1382);
#1384=EDGE_CURVE('E646',#1383,#1375,#1381,.T.);
#1385=ORIENTED_EDGE('',*,*,#1384,.F.);
#1386=DIRECTION('',(0.,0.,-1.));
#1387=VECTOR('',#1386,1.);
#1388=CARTESIAN_POINT('',(-6.4,-12.5,4.4));
#1389=LINE('',#1388,#1387);
#1390=CARTESIAN_POINT('',(-6.4,-12.5,4.));
#1391=VERTEX_POINT('',#1390);
#1392=EDGE_CURVE('E573',#1391,#1383,#1389,.T.);
#1393=ORIENTED_EDGE('',*,*,#1392,.F.);
#1394=EDGE_CURVE('E525',#992,#1391,#45,.T.);
#1395=ORIENTED_EDGE('',*,*,#1394,.F.);
#1396=EDGE_LOOP('',(#1009,#1015,#1016,#1022,#1023,#1024,#1032,#1040,#1046,#1047,#1055,#1063,
#1069,#1070,#1078,#1086,#1092,#1093,#1101,#1109,#1115,#1116,#1124,#1132,#1138,#1139,#1147,#1155,
#1161,#1162,#1170,#1178,#1184,#1185,#1193,#1201,#1207,#1208,#1216,#1224,#1230,#1231,#1239,#1247,
#1253,#1254,#1262,#1270,#1276,#1277,#1285,#1293,#1299,#1300,#1308,#1316,#1322,#1323,#1331,#1339,
#1345,#1346,#1354,#1362,#1368,#1369,#1377,#1385,#1393,#1395));
#1397=FACE_BOUND('',#1396,.T.);
#1398=ADVANCED_FACE('F509',(#1397),#1008,.F.);
#1399=ORIENTED_EDGE('',*,*,#1394,.T.);
#1400=DIRECTION('',(0.,-1.,0.));
#1401=VECTOR('',#1400,1.);
#1402=CARTESIAN_POINT('',(-6.4,-12.501,4.));
#1403=LINE('',#1402,#1401);
#1404=EDGE_CURVE('E577',#592,#1391,#1403,.T.);
#1405=ORIENTED_EDGE('',*,*,#1404,.F.);
#1406=ORIENTED_EDGE('',*,*,#593,.T.);
#1407=ORIENTED_EDGE('',*,*,#999,.T.);
#1408=EDGE_LOOP('',(#1399,#1405,#1406,#1407));
#1409=FACE_BOUND('',#1408,.T.);
#1410=ADVANCED_FACE('F576',(#1409),#23,.F.);
#1411=CARTESIAN_POINT('',(25.,-12.5,2.3094010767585));
#1412=DIRECTION('',(0.499999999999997,0.,-0.86602540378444));
#1413=DIRECTION('',(0.,-1.,0.));
#1414=AXIS2_PLACEMENT_3D('',#1411,#1412,#1413);
#1415=PLANE('',#1414);
#1416=ORIENTED_EDGE('',*,*,#1021,.F.);
#1417=ORIENTED_EDGE('',*,*,#499,.F.);
#1418=ORIENTED_EDGE('',*,*,#968,.F.);
#1419=ORIENTED_EDGE('',*,*,#557,.F.);
#1420=EDGE_LOOP('',(#1416,#1417,#1418,#1419));
#1421=FACE_BOUND('',#1420,.T.);
#1422=ADVANCED_FACE('F996',(#1421),#1415,.T.);
#1423=CARTESIAN_POINT('',(5.,-5.,-5.5));
#1424=DIRECTION('',(1.,0.,0.));
#1425=DIRECTION('',(0.,0.,-1.));
#1426=AXIS2_PLACEMENT_3D('',#1423,#1424,#1425);
#1427=PLANE('',#1426);
#1428=ORIENTED_EDGE('',*,*,#519,.T.);
#1429=DIRECTION('',(0.,0.,1.));
#1430=VECTOR('',#1429,1.);
#1431=CARTESIAN_POINT('',(5.,5.,-5.5));
#1432=LINE('',#1431,#1430);
#1433=CARTESIAN_POINT('',(5.,5.,-5.5));
#1434=VERTEX_POINT('',#1433);
#1435=EDGE_CURVE('E536',#1434,#508,#1432,.T.);
#1436=ORIENTED_EDGE('',*,*,#1435,.F.);
#1437=DIRECTION('',(0.,1.,0.));
#1438=VECTOR('',#1437,1.);
#1439=CARTESIAN_POINT('',(5.,-5.,-5.5));
#1440=LINE('',#1439,#1438);
#1441=CARTESIAN_POINT('',(5.,-5.,-5.5));
#1442=VERTEX_POINT('',#1441);
#1443=EDGE_CURVE('E607',#1442,#1434,#1440,.T.);
#1444=ORIENTED_EDGE('',*,*,#1443,.F.);
#1445=DIRECTION('',(0.,0.,1.));
#1446=VECTOR('',#1445,1.);
#1447=CARTESIAN_POINT('',(5.,-5.,-5.5));
#1448=LINE('',#1447,#1446);
#1449=EDGE_CURVE('E601',#1442,#518,#1448,.T.);
#1450=ORIENTED_EDGE('',*,*,#1449,.T.);
#1451=EDGE_LOOP('',(#1428,#1436,#1444,#1450));
#1452=FACE_BOUND('',#1451,.T.);
#1453=ADVANCED_FACE('F1021',(#1452),#1427,.F.);
#1454=CARTESIAN_POINT('',(15.,5.,-5.5));
#1455=DIRECTION('',(0.,-1.,0.));
#1456=DIRECTION('',(0.,0.,-1.));
#1457=AXIS2_PLACEMENT_3D('',#1454,#1455,#1456);
#1458=PLANE('',#1457);
#1459=ORIENTED_EDGE('',*,*,#511,.T.);
#1460=DIRECTION('',(0.,0.,1.));
#1461=VECTOR('',#1460,1.);
#1462=CARTESIAN_POINT('',(15.,5.,-5.5));
#1463=LINE('',#1462,#1461);
#1464=CARTESIAN_POINT('',(15.,5.,-5.5));
#1465=VERTEX_POINT('',#1464);
#1466=EDGE_CURVE('E596',#1465,#510,#1463,.T.);
#1467=ORIENTED_EDGE('',*,*,#1466,.F.);
#1468=DIRECTION('',(1.,0.,0.));
#1469=VECTOR('',#1468,1.);
#1470=CARTESIAN_POINT('',(15.,5.,-5.5));
#1471=LINE('',#1470,#1469);
#1472=EDGE_CURVE('E620',#1434,#1465,#1471,.T.);
#1473=ORIENTED_EDGE('',*,*,#1472,.F.);
#1474=ORIENTED_EDGE('',*,*,#1435,.T.);
#1475=EDGE_LOOP('',(#1459,#1467,#1473,#1474));
#1476=FACE_BOUND('',#1475,.T.);
#1477=ADVANCED_FACE('F1411',(#1476),#1458,.F.);
#1478=CARTESIAN_POINT('',(15.,-5.,-5.5));
#1479=DIRECTION('',(-1.,0.,0.));
#1480=DIRECTION('',(0.,0.,1.));
#1481=AXIS2_PLACEMENT_3D('',#1478,#1479,#1480);
#1482=PLANE('',#1481);
#1483=ORIENTED_EDGE('',*,*,#533,.T.);
#1484=DIRECTION('',(0.,0.,1.));
#1485=VECTOR('',#1484,1.);
#1486=CARTESIAN_POINT('',(15.,-5.,-5.5));
#1487=LINE('',#1486,#1485);
#1488=CARTESIAN_POINT('',(15.,-5.,-5.5));
#1489=VERTEX_POINT('',#1488);
#1490=EDGE_CURVE('E599',#1489,#526,#1487,.T.);
#1491=ORIENTED_EDGE('',*,*,#1490,.F.);
#1492=DIRECTION('',(0.,-1.,0.));
#1493=VECTOR('',#1492,1.);
#1494=CARTESIAN_POINT('',(15.,-5.,-5.5));
#1495=LINE('',#1494,#1493);
#1496=EDGE_CURVE('E618',#1465,#1489,#1495,.T.);
#1497=ORIENTED_EDGE('',*,*,#1496,.F.);
#1498=ORIENTED_EDGE('',*,*,#1466,.T.);
#1499=EDGE_LOOP('',(#1483,#1491,#1497,#1498));
#1500=FACE_BOUND('',#1499,.T.);
#1501=ADVANCED_FACE('F1407',(#1500),#1482,.F.);
#1502=CARTESIAN_POINT('',(15.,-5.,-5.5));
#1503=DIRECTION('',(0.,1.,0.));
#1504=DIRECTION('',(0.,0.,1.));
#1505=AXIS2_PLACEMENT_3D('',#1502,#1503,#1504);
#1506=PLANE('',#1505);
#1507=ORIENTED_EDGE('',*,*,#527,.T.);
#1508=ORIENTED_EDGE('',*,*,#1449,.F.);
#1509=DIRECTION('',(-1.,0.,0.));
#1510=VECTOR('',#1509,1.);
#1511=CARTESIAN_POINT('',(15.,-5.,-5.5));
#1512=LINE('',#1511,#1510);
#1513=EDGE_CURVE('E604',#1489,#1442,#1512,.T.);
#1514=ORIENTED_EDGE('',*,*,#1513,.F.);
#1515=ORIENTED_EDGE('',*,*,#1490,.T.);
#1516=EDGE_LOOP('',(#1507,#1508,#1514,#1515));
#1517=FACE_BOUND('',#1516,.T.);
#1518=ADVANCED_FACE('F1403',(#1517),#1506,.F.);
#1519=CARTESIAN_POINT('',(0.,0.,-5.5));
#1520=DIRECTION('',(0.,0.,1.));
#1521=DIRECTION('',(1.,0.,0.));
#1522=AXIS2_PLACEMENT_3D('',#1519,#1520,#1521);
#1523=PLANE('',#1522);
#1524=ORIENTED_EDGE('',*,*,#1443,.T.);
#1525=ORIENTED_EDGE('',*,*,#1472,.T.);
#1526=ORIENTED_EDGE('',*,*,#1496,.T.);
#1527=ORIENTED_EDGE('',*,*,#1513,.T.);
#1528=EDGE_LOOP('',(#1524,#1525,#1526,#1527));
#1529=FACE_BOUND('',#1528,.T.);
#1530=ADVANCED_FACE('F1400',(#1529),#1523,.F.);
#1531=CARTESIAN_POINT('',(24.4,-12.501,4.4));
#1532=DIRECTION('',(1.,0.,0.));
#1533=DIRECTION('',(0.,0.,-1.));
#1534=AXIS2_PLACEMENT_3D('',#1531,#1532,#1533);
#1535=PLANE('',#1534);
#1536=ORIENTED_EDGE('',*,*,#1031,.T.);
#1537=ORIENTED_EDGE('',*,*,#449,.T.);
#1538=ORIENTED_EDGE('',*,*,#960,.T.);
#1539=DIRECTION('',(0.,1.,0.));
#1540=VECTOR('',#1539,1.);
#1541=CARTESIAN_POINT('',(24.4,-12.501,3.6));
#1542=LINE('',#1541,#1540);
#1543=EDGE_CURVE('E626',#1030,#953,#1542,.T.);
#1544=ORIENTED_EDGE('',*,*,#1543,.F.);
#1545=EDGE_LOOP('',(#1536,#1537,#1538,#1544));
#1546=FACE_BOUND('',#1545,.T.);
#1547=ADVANCED_FACE('F987',(#1546),#1535,.F.);
#1548=CARTESIAN_POINT('',(23.6,-12.501,4.4));
#1549=DIRECTION('',(-1.,0.,0.));
#1550=DIRECTION('',(0.,0.,1.));
#1551=AXIS2_PLACEMENT_3D('',#1548,#1549,#1550);
#1552=PLANE('',#1551);
#1553=ORIENTED_EDGE('',*,*,#1045,.T.);
#1554=DIRECTION('',(0.,1.,0.));
#1555=VECTOR('',#1554,1.);
#1556=CARTESIAN_POINT('',(23.6,-12.501,3.6));
#1557=LINE('',#1556,#1555);
#1558=EDGE_CURVE('E625',#1038,#945,#1557,.T.);
#1559=ORIENTED_EDGE('',*,*,#1558,.T.);
#1560=ORIENTED_EDGE('',*,*,#946,.T.);
#1561=ORIENTED_EDGE('',*,*,#54,.T.);
#1562=EDGE_LOOP('',(#1553,#1559,#1560,#1561));
#1563=FACE_BOUND('',#1562,.T.);
#1564=ADVANCED_FACE('F978',(#1563),#1552,.F.);
#1565=CARTESIAN_POINT('',(23.6,-12.501,3.6));
#1566=DIRECTION('',(0.,0.,-1.));
#1567=DIRECTION('',(-1.,0.,0.));
#1568=AXIS2_PLACEMENT_3D('',#1565,#1566,#1567);
#1569=PLANE('',#1568);
#1570=ORIENTED_EDGE('',*,*,#1039,.T.);
#1571=ORIENTED_EDGE('',*,*,#1543,.T.);
#1572=ORIENTED_EDGE('',*,*,#954,.T.);
#1573=ORIENTED_EDGE('',*,*,#1558,.F.);
#1574=EDGE_LOOP('',(#1570,#1571,#1572,#1573));
#1575=FACE_BOUND('',#1574,.T.);
#1576=ADVANCED_FACE('F985',(#1575),#1569,.F.);
#1577=CARTESIAN_POINT('',(-5.6,-12.501,4.4));
#1578=DIRECTION('',(1.,0.,0.));
#1579=DIRECTION('',(0.,0.,-1.));
#1580=AXIS2_PLACEMENT_3D('',#1577,#1578,#1579);
#1581=PLANE('',#1580);
#1582=ORIENTED_EDGE('',*,*,#1376,.T.);
#1583=ORIENTED_EDGE('',*,*,#432,.T.);
#1584=ORIENTED_EDGE('',*,*,#615,.T.);
#1585=DIRECTION('',(0.,1.,0.));
#1586=VECTOR('',#1585,1.);
#1587=CARTESIAN_POINT('',(-5.6,-12.501,3.6));
#1588=LINE('',#1587,#1586);
#1589=EDGE_CURVE('E650',#1375,#608,#1588,.T.);
#1590=ORIENTED_EDGE('',*,*,#1589,.F.);
#1591=EDGE_LOOP('',(#1582,#1583,#1584,#1590));
#1592=FACE_BOUND('',#1591,.T.);
#1593=ADVANCED_FACE('F1386',(#1592),#1581,.F.);
#1594=CARTESIAN_POINT('',(-6.4,-12.501,4.4));
#1595=DIRECTION('',(-1.,0.,0.));
#1596=DIRECTION('',(0.,0.,1.));
#1597=AXIS2_PLACEMENT_3D('',#1594,#1595,#1596);
#1598=PLANE('',#1597);
#1599=ORIENTED_EDGE('',*,*,#1392,.T.);
#1600=DIRECTION('',(0.,1.,0.));
#1601=VECTOR('',#1600,1.);
#1602=CARTESIAN_POINT('',(-6.4,-12.501,3.6));
#1603=LINE('',#1602,#1601);
#1604=EDGE_CURVE('E649',#1383,#600,#1603,.T.);
#1605=ORIENTED_EDGE('',*,*,#1604,.T.);
#1606=ORIENTED_EDGE('',*,*,#601,.T.);
#1607=ORIENTED_EDGE('',*,*,#1404,.T.);
#1608=EDGE_LOOP('',(#1599,#1605,#1606,#1607));
#1609=FACE_BOUND('',#1608,.T.);
#1610=ADVANCED_FACE('F1383',(#1609),#1598,.F.);
#1611=CARTESIAN_POINT('',(-6.4,-12.501,3.6));
#1612=DIRECTION('',(0.,0.,-1.));
#1613=DIRECTION('',(-1.,0.,0.));
#1614=AXIS2_PLACEMENT_3D('',#1611,#1612,#1613);
#1615=PLANE('',#1614);
#1616=ORIENTED_EDGE('',*,*,#1384,.T.);
#1617=ORIENTED_EDGE('',*,*,#1589,.T.);
#1618=ORIENTED_EDGE('',*,*,#609,.T.);
#1619=ORIENTED_EDGE('',*,*,#1604,.F.);
#1620=EDGE_LOOP('',(#1616,#1617,#1618,#1619));
#1621=FACE_BOUND('',#1620,.T.);
#1622=ADVANCED_FACE('F1382',(#1621),#1615,.F.);
#1623=CARTESIAN_POINT('',(-3.6,-12.501,4.4));
#1624=DIRECTION('',(1.,0.,0.));
#1625=DIRECTION('',(0.,0.,-1.));
#1626=AXIS2_PLACEMENT_3D('',#1623,#1624,#1625);
#1627=PLANE('',#1626);
#1628=ORIENTED_EDGE('',*,*,#1353,.T.);
#1629=ORIENTED_EDGE('',*,*,#405,.T.);
#1630=ORIENTED_EDGE('',*,*,#638,.T.);
#1631=DIRECTION('',(0.,1.,0.));
#1632=VECTOR('',#1631,1.);
#1633=CARTESIAN_POINT('',(-3.6,-12.501,3.6));
#1634=LINE('',#1633,#1632);
#1635=EDGE_CURVE('E671',#1352,#631,#1634,.T.);
#1636=ORIENTED_EDGE('',*,*,#1635,.F.);
#1637=EDGE_LOOP('',(#1628,#1629,#1630,#1636));
#1638=FACE_BOUND('',#1637,.T.);
#1639=ADVANCED_FACE('F1165',(#1638),#1627,.F.);
#1640=CARTESIAN_POINT('',(-4.4,-12.501,4.4));
#1641=DIRECTION('',(-1.,0.,0.));
#1642=DIRECTION('',(0.,0.,1.));
#1643=AXIS2_PLACEMENT_3D('',#1640,#1641,#1642);
#1644=PLANE('',#1643);
#1645=ORIENTED_EDGE('',*,*,#1367,.T.);
#1646=DIRECTION('',(0.,1.,0.));
#1647=VECTOR('',#1646,1.);
#1648=CARTESIAN_POINT('',(-4.4,-12.501,3.6));
#1649=LINE('',#1648,#1647);
#1650=EDGE_CURVE('E670',#1360,#623,#1649,.T.);
#1651=ORIENTED_EDGE('',*,*,#1650,.T.);
#1652=ORIENTED_EDGE('',*,*,#624,.T.);
#1653=ORIENTED_EDGE('',*,*,#422,.T.);
#1654=EDGE_LOOP('',(#1645,#1651,#1652,#1653));
#1655=FACE_BOUND('',#1654,.T.);
#1656=ADVANCED_FACE('F1373',(#1655),#1644,.F.);
#1657=CARTESIAN_POINT('',(-4.4,-12.501,3.6));
#1658=DIRECTION('',(0.,0.,-1.));
#1659=DIRECTION('',(-1.,0.,0.));
#1660=AXIS2_PLACEMENT_3D('',#1657,#1658,#1659);
#1661=PLANE('',#1660);
#1662=ORIENTED_EDGE('',*,*,#1361,.T.);
#1663=ORIENTED_EDGE('',*,*,#1635,.T.);
#1664=ORIENTED_EDGE('',*,*,#632,.T.);
#1665=ORIENTED_EDGE('',*,*,#1650,.F.);
#1666=EDGE_LOOP('',(#1662,#1663,#1664,#1665));
#1667=FACE_BOUND('',#1666,.T.);
#1668=ADVANCED_FACE('F1372',(#1667),#1661,.F.);
#1669=CARTESIAN_POINT('',(-1.6,-12.501,4.4));
#1670=DIRECTION('',(1.,0.,0.));
#1671=DIRECTION('',(0.,0.,-1.));
#1672=AXIS2_PLACEMENT_3D('',#1669,#1670,#1671);
#1673=PLANE('',#1672);
#1674=ORIENTED_EDGE('',*,*,#1330,.T.);
#1675=ORIENTED_EDGE('',*,*,#378,.T.);
#1676=ORIENTED_EDGE('',*,*,#661,.T.);
#1677=DIRECTION('',(0.,1.,0.));
#1678=VECTOR('',#1677,1.);
#1679=CARTESIAN_POINT('',(-1.6,-12.501,3.6));
#1680=LINE('',#1679,#1678);
#1681=EDGE_CURVE('E693',#1329,#654,#1680,.T.);
#1682=ORIENTED_EDGE('',*,*,#1681,.F.);
#1683=EDGE_LOOP('',(#1674,#1675,#1676,#1682));
#1684=FACE_BOUND('',#1683,.T.);
#1685=ADVANCED_FACE('F1180',(#1684),#1673,.F.);
#1686=CARTESIAN_POINT('',(-2.4,-12.501,4.4));
#1687=DIRECTION('',(-1.,0.,0.));
#1688=DIRECTION('',(0.,0.,1.));
#1689=AXIS2_PLACEMENT_3D('',#1686,#1687,#1688);
#1690=PLANE('',#1689);
#1691=ORIENTED_EDGE('',*,*,#1344,.T.);
#1692=DIRECTION('',(0.,1.,0.));
#1693=VECTOR('',#1692,1.);
#1694=CARTESIAN_POINT('',(-2.4,-12.501,3.6));
#1695=LINE('',#1694,#1693);
#1696=EDGE_CURVE('E692',#1337,#646,#1695,.T.);
#1697=ORIENTED_EDGE('',*,*,#1696,.T.);
#1698=ORIENTED_EDGE('',*,*,#647,.T.);
#1699=ORIENTED_EDGE('',*,*,#395,.T.);
#1700=EDGE_LOOP('',(#1691,#1697,#1698,#1699));
#1701=FACE_BOUND('',#1700,.T.);
#1702=ADVANCED_FACE('F1173',(#1701),#1690,.F.);
#1703=CARTESIAN_POINT('',(-2.4,-12.501,3.6));
#1704=DIRECTION('',(0.,0.,-1.));
#1705=DIRECTION('',(-1.,0.,0.));
#1706=AXIS2_PLACEMENT_3D('',#1703,#1704,#1705);
#1707=PLANE('',#1706);
#1708=ORIENTED_EDGE('',*,*,#1338,.T.);
#1709=ORIENTED_EDGE('',*,*,#1681,.T.);
#1710=ORIENTED_EDGE('',*,*,#655,.T.);
#1711=ORIENTED_EDGE('',*,*,#1696,.F.);
#1712=EDGE_LOOP('',(#1708,#1709,#1710,#1711));
#1713=FACE_BOUND('',#1712,.T.);
#1714=ADVANCED_FACE('F1175',(#1713),#1707,.F.);
#1715=CARTESIAN_POINT('',(0.399999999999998,-12.501,4.4));
#1716=DIRECTION('',(1.,0.,0.));
#1717=DIRECTION('',(0.,0.,-1.));
#1718=AXIS2_PLACEMENT_3D('',#1715,#1716,#1717);
#1719=PLANE('',#1718);
#1720=ORIENTED_EDGE('',*,*,#1307,.T.);
#1721=ORIENTED_EDGE('',*,*,#351,.T.);
#1722=ORIENTED_EDGE('',*,*,#684,.T.);
#1723=DIRECTION('',(0.,1.,0.));
#1724=VECTOR('',#1723,1.);
#1725=CARTESIAN_POINT('',(0.399999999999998,-12.501,3.6));
#1726=LINE('',#1725,#1724);
#1727=EDGE_CURVE('E715',#1306,#677,#1726,.T.);
#1728=ORIENTED_EDGE('',*,*,#1727,.F.);
#1729=EDGE_LOOP('',(#1720,#1721,#1722,#1728));
#1730=FACE_BOUND('',#1729,.T.);
#1731=ADVANCED_FACE('F1194',(#1730),#1719,.F.);
#1732=CARTESIAN_POINT('',(-0.400000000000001,-12.501,4.4));
#1733=DIRECTION('',(-1.,0.,0.));
#1734=DIRECTION('',(0.,0.,1.));
#1735=AXIS2_PLACEMENT_3D('',#1732,#1733,#1734);
#1736=PLANE('',#1735);
#1737=ORIENTED_EDGE('',*,*,#1321,.T.);
#1738=DIRECTION('',(0.,1.,0.));
#1739=VECTOR('',#1738,1.);
#1740=CARTESIAN_POINT('',(-0.400000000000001,-12.501,3.6));
#1741=LINE('',#1740,#1739);
#1742=EDGE_CURVE('E714',#1314,#669,#1741,.T.);
#1743=ORIENTED_EDGE('',*,*,#1742,.T.);
#1744=ORIENTED_EDGE('',*,*,#670,.T.);
#1745=ORIENTED_EDGE('',*,*,#368,.T.);
#1746=EDGE_LOOP('',(#1737,#1743,#1744,#1745));
#1747=FACE_BOUND('',#1746,.T.);
#1748=ADVANCED_FACE('F1186',(#1747),#1736,.F.);
#1749=CARTESIAN_POINT('',(-0.400000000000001,-12.501,3.6));
#1750=DIRECTION('',(0.,0.,-1.));
#1751=DIRECTION('',(-1.,0.,0.));
#1752=AXIS2_PLACEMENT_3D('',#1749,#1750,#1751);
#1753=PLANE('',#1752);
#1754=ORIENTED_EDGE('',*,*,#1315,.T.);
#1755=ORIENTED_EDGE('',*,*,#1727,.T.);
#1756=ORIENTED_EDGE('',*,*,#678,.T.);
#1757=ORIENTED_EDGE('',*,*,#1742,.F.);
#1758=EDGE_LOOP('',(#1754,#1755,#1756,#1757));
#1759=FACE_BOUND('',#1758,.T.);
#1760=ADVANCED_FACE('F1188',(#1759),#1753,.F.);
#1761=CARTESIAN_POINT('',(2.4,-12.501,4.4));
#1762=DIRECTION('',(1.,0.,0.));
#1763=DIRECTION('',(0.,0.,-1.));
#1764=AXIS2_PLACEMENT_3D('',#1761,#1762,#1763);
#1765=PLANE('',#1764);
#1766=ORIENTED_EDGE('',*,*,#1284,.T.);
#1767=ORIENTED_EDGE('',*,*,#324,.T.);
#1768=ORIENTED_EDGE('',*,*,#707,.T.);
#1769=DIRECTION('',(0.,1.,0.));
#1770=VECTOR('',#1769,1.);
#1771=CARTESIAN_POINT('',(2.4,-12.501,3.6));
#1772=LINE('',#1771,#1770);
#1773=EDGE_CURVE('E737',#1283,#700,#1772,.T.);
#1774=ORIENTED_EDGE('',*,*,#1773,.F.);
#1775=EDGE_LOOP('',(#1766,#1767,#1768,#1774));
#1776=FACE_BOUND('',#1775,.T.);
#1777=ADVANCED_FACE('F1209',(#1776),#1765,.F.);
#1778=CARTESIAN_POINT('',(1.6,-12.501,4.4));
#1779=DIRECTION('',(-1.,0.,0.));
#1780=DIRECTION('',(0.,0.,1.));
#1781=AXIS2_PLACEMENT_3D('',#1778,#1779,#1780);
#1782=PLANE('',#1781);
#1783=ORIENTED_EDGE('',*,*,#1298,.T.);
#1784=DIRECTION('',(0.,1.,0.));
#1785=VECTOR('',#1784,1.);
#1786=CARTESIAN_POINT('',(1.6,-12.501,3.6));
#1787=LINE('',#1786,#1785);
#1788=EDGE_CURVE('E736',#1291,#692,#1787,.T.);
#1789=ORIENTED_EDGE('',*,*,#1788,.T.);
#1790=ORIENTED_EDGE('',*,*,#693,.T.);
#1791=ORIENTED_EDGE('',*,*,#341,.T.);
#1792=EDGE_LOOP('',(#1783,#1789,#1790,#1791));
#1793=FACE_BOUND('',#1792,.T.);
#1794=ADVANCED_FACE('F1201',(#1793),#1782,.F.);
#1795=CARTESIAN_POINT('',(1.6,-12.501,3.6));
#1796=DIRECTION('',(0.,0.,-1.));
#1797=DIRECTION('',(-1.,0.,0.));
#1798=AXIS2_PLACEMENT_3D('',#1795,#1796,#1797);
#1799=PLANE('',#1798);
#1800=ORIENTED_EDGE('',*,*,#1292,.T.);
#1801=ORIENTED_EDGE('',*,*,#1773,.T.);
#1802=ORIENTED_EDGE('',*,*,#701,.T.);
#1803=ORIENTED_EDGE('',*,*,#1788,.F.);
#1804=EDGE_LOOP('',(#1800,#1801,#1802,#1803));
#1805=FACE_BOUND('',#1804,.T.);
#1806=ADVANCED_FACE('F1203',(#1805),#1799,.F.);
#1807=CARTESIAN_POINT('',(4.4,-12.501,4.4));
#1808=DIRECTION('',(1.,0.,0.));
#1809=DIRECTION('',(0.,0.,-1.));
#1810=AXIS2_PLACEMENT_3D('',#1807,#1808,#1809);
#1811=PLANE('',#1810);
#1812=ORIENTED_EDGE('',*,*,#1261,.T.);
#1813=ORIENTED_EDGE('',*,*,#297,.T.);
#1814=ORIENTED_EDGE('',*,*,#730,.T.);
#1815=DIRECTION('',(0.,1.,0.));
#1816=VECTOR('',#1815,1.);
#1817=CARTESIAN_POINT('',(4.4,-12.501,3.6));
#1818=LINE('',#1817,#1816);
#1819=EDGE_CURVE('E759',#1260,#723,#1818,.T.);
#1820=ORIENTED_EDGE('',*,*,#1819,.F.);
#1821=EDGE_LOOP('',(#1812,#1813,#1814,#1820));
#1822=FACE_BOUND('',#1821,.T.);
#1823=ADVANCED_FACE('F1224',(#1822),#1811,.F.);
#1824=CARTESIAN_POINT('',(3.6,-12.501,4.4));
#1825=DIRECTION('',(-1.,0.,0.));
#1826=DIRECTION('',(0.,0.,1.));
#1827=AXIS2_PLACEMENT_3D('',#1824,#1825,#1826);
#1828=PLANE('',#1827);
#1829=ORIENTED_EDGE('',*,*,#1275,.T.);
#1830=DIRECTION('',(0.,1.,0.));
#1831=VECTOR('',#1830,1.);
#1832=CARTESIAN_POINT('',(3.6,-12.501,3.6));
#1833=LINE('',#1832,#1831);
#1834=EDGE_CURVE('E758',#1268,#715,#1833,.T.);
#1835=ORIENTED_EDGE('',*,*,#1834,.T.);
#1836=ORIENTED_EDGE('',*,*,#716,.T.);
#1837=ORIENTED_EDGE('',*,*,#314,.T.);
#1838=EDGE_LOOP('',(#1829,#1835,#1836,#1837));
#1839=FACE_BOUND('',#1838,.T.);
#1840=ADVANCED_FACE('F1216',(#1839),#1828,.F.);
#1841=CARTESIAN_POINT('',(3.6,-12.501,3.6));
#1842=DIRECTION('',(0.,0.,-1.));
#1843=DIRECTION('',(-1.,0.,0.));
#1844=AXIS2_PLACEMENT_3D('',#1841,#1842,#1843);
#1845=PLANE('',#1844);
#1846=ORIENTED_EDGE('',*,*,#1269,.T.);
#1847=ORIENTED_EDGE('',*,*,#1819,.T.);
#1848=ORIENTED_EDGE('',*,*,#724,.T.);
#1849=ORIENTED_EDGE('',*,*,#1834,.F.);
#1850=EDGE_LOOP('',(#1846,#1847,#1848,#1849));
#1851=FACE_BOUND('',#1850,.T.);
#1852=ADVANCED_FACE('F1218',(#1851),#1845,.F.);
#1853=CARTESIAN_POINT('',(6.4,-12.501,4.4));
#1854=DIRECTION('',(1.,0.,0.));
#1855=DIRECTION('',(0.,0.,-1.));
#1856=AXIS2_PLACEMENT_3D('',#1853,#1854,#1855);
#1857=PLANE('',#1856);
#1858=ORIENTED_EDGE('',*,*,#1238,.T.);
#1859=ORIENTED_EDGE('',*,*,#270,.T.);
#1860=ORIENTED_EDGE('',*,*,#753,.T.);
#1861=DIRECTION('',(0.,1.,0.));
#1862=VECTOR('',#1861,1.);
#1863=CARTESIAN_POINT('',(6.4,-12.501,3.6));
#1864=LINE('',#1863,#1862);
#1865=EDGE_CURVE('E781',#1237,#746,#1864,.T.);
#1866=ORIENTED_EDGE('',*,*,#1865,.F.);
#1867=EDGE_LOOP('',(#1858,#1859,#1860,#1866));
#1868=FACE_BOUND('',#1867,.T.);
#1869=ADVANCED_FACE('F1239',(#1868),#1857,.F.);
#1870=CARTESIAN_POINT('',(5.6,-12.501,4.4));
#1871=DIRECTION('',(-1.,0.,0.));
#1872=DIRECTION('',(0.,0.,1.));
#1873=AXIS2_PLACEMENT_3D('',#1870,#1871,#1872);
#1874=PLANE('',#1873);
#1875=ORIENTED_EDGE('',*,*,#1252,.T.);
#1876=DIRECTION('',(0.,1.,0.));
#1877=VECTOR('',#1876,1.);
#1878=CARTESIAN_POINT('',(5.6,-12.501,3.6));
#1879=LINE('',#1878,#1877);
#1880=EDGE_CURVE('E780',#1245,#738,#1879,.T.);
#1881=ORIENTED_EDGE('',*,*,#1880,.T.);
#1882=ORIENTED_EDGE('',*,*,#739,.T.);
#1883=ORIENTED_EDGE('',*,*,#287,.T.);
#1884=EDGE_LOOP('',(#1875,#1881,#1882,#1883));
#1885=FACE_BOUND('',#1884,.T.);
#1886=ADVANCED_FACE('F1231',(#1885),#1874,.F.);
#1887=CARTESIAN_POINT('',(5.6,-12.501,3.6));
#1888=DIRECTION('',(0.,0.,-1.));
#1889=DIRECTION('',(-1.,0.,0.));
#1890=AXIS2_PLACEMENT_3D('',#1887,#1888,#1889);
#1891=PLANE('',#1890);
#1892=ORIENTED_EDGE('',*,*,#1246,.T.);
#1893=ORIENTED_EDGE('',*,*,#1865,.T.);
#1894=ORIENTED_EDGE('',*,*,#747,.T.);
#1895=ORIENTED_EDGE('',*,*,#1880,.F.);
#1896=EDGE_LOOP('',(#1892,#1893,#1894,#1895));
#1897=FACE_BOUND('',#1896,.T.);
#1898=ADVANCED_FACE('F1233',(#1897),#1891,.F.);
#1899=CARTESIAN_POINT('',(8.4,-12.501,4.4));
#1900=DIRECTION('',(1.,0.,0.));
#1901=DIRECTION('',(0.,0.,-1.));
#1902=AXIS2_PLACEMENT_3D('',#1899,#1900,#1901);
#1903=PLANE('',#1902);
#1904=ORIENTED_EDGE('',*,*,#1215,.T.);
#1905=ORIENTED_EDGE('',*,*,#243,.T.);
#1906=ORIENTED_EDGE('',*,*,#776,.T.);
#1907=DIRECTION('',(0.,1.,0.));
#1908=VECTOR('',#1907,1.);
#1909=CARTESIAN_POINT('',(8.4,-12.501,3.6));
#1910=LINE('',#1909,#1908);
#1911=EDGE_CURVE('E803',#1214,#769,#1910,.T.);
#1912=ORIENTED_EDGE('',*,*,#1911,.F.);
#1913=EDGE_LOOP('',(#1904,#1905,#1906,#1912));
#1914=FACE_BOUND('',#1913,.T.);
#1915=ADVANCED_FACE('F1254',(#1914),#1903,.F.);
#1916=CARTESIAN_POINT('',(7.6,-12.501,4.4));
#1917=DIRECTION('',(-1.,0.,0.));
#1918=DIRECTION('',(0.,0.,1.));
#1919=AXIS2_PLACEMENT_3D('',#1916,#1917,#1918);
#1920=PLANE('',#1919);
#1921=ORIENTED_EDGE('',*,*,#1229,.T.);
#1922=DIRECTION('',(0.,1.,0.));
#1923=VECTOR('',#1922,1.);
#1924=CARTESIAN_POINT('',(7.6,-12.501,3.6));
#1925=LINE('',#1924,#1923);
#1926=EDGE_CURVE('E802',#1222,#761,#1925,.T.);
#1927=ORIENTED_EDGE('',*,*,#1926,.T.);
#1928=ORIENTED_EDGE('',*,*,#762,.T.);
#1929=ORIENTED_EDGE('',*,*,#260,.T.);
#1930=EDGE_LOOP('',(#1921,#1927,#1928,#1929));
#1931=FACE_BOUND('',#1930,.T.);
#1932=ADVANCED_FACE('F1246',(#1931),#1920,.F.);
#1933=CARTESIAN_POINT('',(7.6,-12.501,3.6));
#1934=DIRECTION('',(0.,0.,-1.));
#1935=DIRECTION('',(-1.,0.,0.));
#1936=AXIS2_PLACEMENT_3D('',#1933,#1934,#1935);
#1937=PLANE('',#1936);
#1938=ORIENTED_EDGE('',*,*,#1223,.T.);
#1939=ORIENTED_EDGE('',*,*,#1911,.T.);
#1940=ORIENTED_EDGE('',*,*,#770,.T.);
#1941=ORIENTED_EDGE('',*,*,#1926,.F.);
#1942=EDGE_LOOP('',(#1938,#1939,#1940,#1941));
#1943=FACE_BOUND('',#1942,.T.);
#1944=ADVANCED_FACE('F1248',(#1943),#1937,.F.);
#1945=CARTESIAN_POINT('',(10.4,-12.501,4.4));
#1946=DIRECTION('',(1.,0.,0.));
#1947=DIRECTION('',(0.,0.,-1.));
#1948=AXIS2_PLACEMENT_3D('',#1945,#1946,#1947);
#1949=PLANE('',#1948);
#1950=ORIENTED_EDGE('',*,*,#1192,.T.);
#1951=ORIENTED_EDGE('',*,*,#216,.T.);
#1952=ORIENTED_EDGE('',*,*,#799,.T.);
#1953=DIRECTION('',(0.,1.,0.));
#1954=VECTOR('',#1953,1.);
#1955=CARTESIAN_POINT('',(10.4,-12.501,3.6));
#1956=LINE('',#1955,#1954);
#1957=EDGE_CURVE('E825',#1191,#792,#1956,.T.);
#1958=ORIENTED_EDGE('',*,*,#1957,.F.);
#1959=EDGE_LOOP('',(#1950,#1951,#1952,#1958));
#1960=FACE_BOUND('',#1959,.T.);
#1961=ADVANCED_FACE('F1269',(#1960),#1949,.F.);
#1962=CARTESIAN_POINT('',(9.6,-12.501,4.4));
#1963=DIRECTION('',(-1.,0.,0.));
#1964=DIRECTION('',(0.,0.,1.));
#1965=AXIS2_PLACEMENT_3D('',#1962,#1963,#1964);
#1966=PLANE('',#1965);
#1967=ORIENTED_EDGE('',*,*,#1206,.T.);
#1968=DIRECTION('',(0.,1.,0.));
#1969=VECTOR('',#1968,1.);
#1970=CARTESIAN_POINT('',(9.6,-12.501,3.6));
#1971=LINE('',#1970,#1969);
#1972=EDGE_CURVE('E824',#1199,#784,#1971,.T.);
#1973=ORIENTED_EDGE('',*,*,#1972,.T.);
#1974=ORIENTED_EDGE('',*,*,#785,.T.);
#1975=ORIENTED_EDGE('',*,*,#233,.T.);
#1976=EDGE_LOOP('',(#1967,#1973,#1974,#1975));
#1977=FACE_BOUND('',#1976,.T.);
#1978=ADVANCED_FACE('F1261',(#1977),#1966,.F.);
#1979=CARTESIAN_POINT('',(9.6,-12.501,3.6));
#1980=DIRECTION('',(0.,0.,-1.));
#1981=DIRECTION('',(-1.,0.,0.));
#1982=AXIS2_PLACEMENT_3D('',#1979,#1980,#1981);
#1983=PLANE('',#1982);
#1984=ORIENTED_EDGE('',*,*,#1200,.T.);
#1985=ORIENTED_EDGE('',*,*,#1957,.T.);
#1986=ORIENTED_EDGE('',*,*,#793,.T.);
#1987=ORIENTED_EDGE('',*,*,#1972,.F.);
#1988=EDGE_LOOP('',(#1984,#1985,#1986,#1987));
#1989=FACE_BOUND('',#1988,.T.);
#1990=ADVANCED_FACE('F1263',(#1989),#1983,.F.);
#1991=CARTESIAN_POINT('',(12.4,-12.501,4.4));
#1992=DIRECTION('',(1.,0.,0.));
#1993=DIRECTION('',(0.,0.,-1.));
#1994=AXIS2_PLACEMENT_3D('',#1991,#1992,#1993);
#1995=PLANE('',#1994);
#1996=ORIENTED_EDGE('',*,*,#1169,.T.);
#1997=ORIENTED_EDGE('',*,*,#189,.T.);
#1998=ORIENTED_EDGE('',*,*,#822,.T.);
#1999=DIRECTION('',(0.,1.,0.));
#2000=VECTOR('',#1999,1.);
#2001=CARTESIAN_POINT('',(12.4,-12.501,3.6));
#2002=LINE('',#2001,#2000);
#2003=EDGE_CURVE('E847',#1168,#815,#2002,.T.);
#2004=ORIENTED_EDGE('',*,*,#2003,.F.);
#2005=EDGE_LOOP('',(#1996,#1997,#1998,#2004));
#2006=FACE_BOUND('',#2005,.T.);
#2007=ADVANCED_FACE('F1284',(#2006),#1995,.F.);
#2008=CARTESIAN_POINT('',(11.6,-12.501,4.4));
#2009=DIRECTION('',(-1.,0.,0.));
#2010=DIRECTION('',(0.,0.,1.));
#2011=AXIS2_PLACEMENT_3D('',#2008,#2009,#2010);
#2012=PLANE('',#2011);
#2013=ORIENTED_EDGE('',*,*,#1183,.T.);
#2014=DIRECTION('',(0.,1.,0.));
#2015=VECTOR('',#2014,1.);
#2016=CARTESIAN_POINT('',(11.6,-12.501,3.6));
#2017=LINE('',#2016,#2015);
#2018=EDGE_CURVE('E846',#1176,#807,#2017,.T.);
#2019=ORIENTED_EDGE('',*,*,#2018,.T.);
#2020=ORIENTED_EDGE('',*,*,#808,.T.);
#2021=ORIENTED_EDGE('',*,*,#206,.T.);
#2022=EDGE_LOOP('',(#2013,#2019,#2020,#2021));
#2023=FACE_BOUND('',#2022,.T.);
#2024=ADVANCED_FACE('F1276',(#2023),#2012,.F.);
#2025=CARTESIAN_POINT('',(11.6,-12.501,3.6));
#2026=DIRECTION('',(0.,0.,-1.));
#2027=DIRECTION('',(-1.,0.,0.));
#2028=AXIS2_PLACEMENT_3D('',#2025,#2026,#2027);
#2029=PLANE('',#2028);
#2030=ORIENTED_EDGE('',*,*,#1177,.T.);
#2031=ORIENTED_EDGE('',*,*,#2003,.T.);
#2032=ORIENTED_EDGE('',*,*,#816,.T.);
#2033=ORIENTED_EDGE('',*,*,#2018,.F.);
#2034=EDGE_LOOP('',(#2030,#2031,#2032,#2033));
#2035=FACE_BOUND('',#2034,.T.);
#2036=ADVANCED_FACE('F1278',(#2035),#2029,.F.);
#2037=CARTESIAN_POINT('',(14.4,-12.501,4.4));
#2038=DIRECTION('',(1.,0.,0.));
#2039=DIRECTION('',(0.,0.,-1.));
#2040=AXIS2_PLACEMENT_3D('',#2037,#2038,#2039);
#2041=PLANE('',#2040);
#2042=ORIENTED_EDGE('',*,*,#1146,.T.);
#2043=ORIENTED_EDGE('',*,*,#162,.T.);
#2044=ORIENTED_EDGE('',*,*,#845,.T.);
#2045=DIRECTION('',(0.,1.,0.));
#2046=VECTOR('',#2045,1.);
#2047=CARTESIAN_POINT('',(14.4,-12.501,3.6));
#2048=LINE('',#2047,#2046);
#2049=EDGE_CURVE('E869',#1145,#838,#2048,.T.);
#2050=ORIENTED_EDGE('',*,*,#2049,.F.);
#2051=EDGE_LOOP('',(#2042,#2043,#2044,#2050));
#2052=FACE_BOUND('',#2051,.T.);
#2053=ADVANCED_FACE('F1299',(#2052),#2041,.F.);
#2054=CARTESIAN_POINT('',(13.6,-12.501,4.4));
#2055=DIRECTION('',(-1.,0.,0.));
#2056=DIRECTION('',(0.,0.,1.));
#2057=AXIS2_PLACEMENT_3D('',#2054,#2055,#2056);
#2058=PLANE('',#2057);
#2059=ORIENTED_EDGE('',*,*,#1160,.T.);
#2060=DIRECTION('',(0.,1.,0.));
#2061=VECTOR('',#2060,1.);
#2062=CARTESIAN_POINT('',(13.6,-12.501,3.6));
#2063=LINE('',#2062,#2061);
#2064=EDGE_CURVE('E868',#1153,#830,#2063,.T.);
#2065=ORIENTED_EDGE('',*,*,#2064,.T.);
#2066=ORIENTED_EDGE('',*,*,#831,.T.);
#2067=ORIENTED_EDGE('',*,*,#179,.T.);
#2068=EDGE_LOOP('',(#2059,#2065,#2066,#2067));
#2069=FACE_BOUND('',#2068,.T.);
#2070=ADVANCED_FACE('F1291',(#2069),#2058,.F.);
#2071=CARTESIAN_POINT('',(13.6,-12.501,3.6));
#2072=DIRECTION('',(0.,0.,-1.));
#2073=DIRECTION('',(-1.,0.,0.));
#2074=AXIS2_PLACEMENT_3D('',#2071,#2072,#2073);
#2075=PLANE('',#2074);
#2076=ORIENTED_EDGE('',*,*,#1154,.T.);
#2077=ORIENTED_EDGE('',*,*,#2049,.T.);
#2078=ORIENTED_EDGE('',*,*,#839,.T.);
#2079=ORIENTED_EDGE('',*,*,#2064,.F.);
#2080=EDGE_LOOP('',(#2076,#2077,#2078,#2079));
#2081=FACE_BOUND('',#2080,.T.);
#2082=ADVANCED_FACE('F1293',(#2081),#2075,.F.);
#2083=CARTESIAN_POINT('',(16.4,-12.501,4.4));
#2084=DIRECTION('',(1.,0.,0.));
#2085=DIRECTION('',(0.,0.,-1.));
#2086=AXIS2_PLACEMENT_3D('',#2083,#2084,#2085);
#2087=PLANE('',#2086);
#2088=ORIENTED_EDGE('',*,*,#1123,.T.);
#2089=ORIENTED_EDGE('',*,*,#135,.T.);
#2090=ORIENTED_EDGE('',*,*,#868,.T.);
#2091=DIRECTION('',(0.,1.,0.));
#2092=VECTOR('',#2091,1.);
#2093=CARTESIAN_POINT('',(16.4,-12.501,3.6));
#2094=LINE('',#2093,#2092);
#2095=EDGE_CURVE('E891',#1122,#861,#2094,.T.);
#2096=ORIENTED_EDGE('',*,*,#2095,.F.);
#2097=EDGE_LOOP('',(#2088,#2089,#2090,#2096));
#2098=FACE_BOUND('',#2097,.T.);
#2099=ADVANCED_FACE('F1309',(#2098),#2087,.F.);
#2100=CARTESIAN_POINT('',(15.6,-12.501,4.4));
#2101=DIRECTION('',(-1.,0.,0.));
#2102=DIRECTION('',(0.,0.,1.));
#2103=AXIS2_PLACEMENT_3D('',#2100,#2101,#2102);
#2104=PLANE('',#2103);
#2105=ORIENTED_EDGE('',*,*,#1137,.T.);
#2106=DIRECTION('',(0.,1.,0.));
#2107=VECTOR('',#2106,1.);
#2108=CARTESIAN_POINT('',(15.6,-12.501,3.6));
#2109=LINE('',#2108,#2107);
#2110=EDGE_CURVE('E890',#1130,#853,#2109,.T.);
#2111=ORIENTED_EDGE('',*,*,#2110,.T.);
#2112=ORIENTED_EDGE('',*,*,#854,.T.);
#2113=ORIENTED_EDGE('',*,*,#152,.T.);
#2114=EDGE_LOOP('',(#2105,#2111,#2112,#2113));
#2115=FACE_BOUND('',#2114,.T.);
#2116=ADVANCED_FACE('F1304',(#2115),#2104,.F.);
#2117=CARTESIAN_POINT('',(15.6,-12.501,3.6));
#2118=DIRECTION('',(0.,0.,-1.));
#2119=DIRECTION('',(-1.,0.,0.));
#2120=AXIS2_PLACEMENT_3D('',#2117,#2118,#2119);
#2121=PLANE('',#2120);
#2122=ORIENTED_EDGE('',*,*,#1131,.T.);
#2123=ORIENTED_EDGE('',*,*,#2095,.T.);
#2124=ORIENTED_EDGE('',*,*,#862,.T.);
#2125=ORIENTED_EDGE('',*,*,#2110,.F.);
#2126=EDGE_LOOP('',(#2122,#2123,#2124,#2125));
#2127=FACE_BOUND('',#2126,.T.);
#2128=ADVANCED_FACE('F1306',(#2127),#2121,.F.);
#2129=CARTESIAN_POINT('',(18.4,-12.501,4.4));
#2130=DIRECTION('',(1.,0.,0.));
#2131=DIRECTION('',(0.,0.,-1.));
#2132=AXIS2_PLACEMENT_3D('',#2129,#2130,#2131);
#2133=PLANE('',#2132);
#2134=ORIENTED_EDGE('',*,*,#1100,.T.);
#2135=ORIENTED_EDGE('',*,*,#108,.T.);
#2136=ORIENTED_EDGE('',*,*,#891,.T.);
#2137=DIRECTION('',(0.,1.,0.));
#2138=VECTOR('',#2137,1.);
#2139=CARTESIAN_POINT('',(18.4,-12.501,3.6));
#2140=LINE('',#2139,#2138);
#2141=EDGE_CURVE('E913',#1099,#884,#2140,.T.);
#2142=ORIENTED_EDGE('',*,*,#2141,.F.);
#2143=EDGE_LOOP('',(#2134,#2135,#2136,#2142));
#2144=FACE_BOUND('',#2143,.T.);
#2145=ADVANCED_FACE('F1611',(#2144),#2133,.F.);
#2146=CARTESIAN_POINT('',(17.6,-12.501,4.4));
#2147=DIRECTION('',(-1.,0.,0.));
#2148=DIRECTION('',(0.,0.,1.));
#2149=AXIS2_PLACEMENT_3D('',#2146,#2147,#2148);
#2150=PLANE('',#2149);
#2151=ORIENTED_EDGE('',*,*,#1114,.T.);
#2152=DIRECTION('',(0.,1.,0.));
#2153=VECTOR('',#2152,1.);
#2154=CARTESIAN_POINT('',(17.6,-12.501,3.6));
#2155=LINE('',#2154,#2153);
#2156=EDGE_CURVE('E912',#1107,#876,#2155,.T.);
#2157=ORIENTED_EDGE('',*,*,#2156,.T.);
#2158=ORIENTED_EDGE('',*,*,#877,.T.);
#2159=ORIENTED_EDGE('',*,*,#125,.T.);
#2160=EDGE_LOOP('',(#2151,#2157,#2158,#2159));
#2161=FACE_BOUND('',#2160,.T.);
#2162=ADVANCED_FACE('F1117',(#2161),#2150,.F.);
#2163=CARTESIAN_POINT('',(17.6,-12.501,3.6));
#2164=DIRECTION('',(0.,0.,-1.));
#2165=DIRECTION('',(-1.,0.,0.));
#2166=AXIS2_PLACEMENT_3D('',#2163,#2164,#2165);
#2167=PLANE('',#2166);
#2168=ORIENTED_EDGE('',*,*,#1108,.T.);
#2169=ORIENTED_EDGE('',*,*,#2141,.T.);
#2170=ORIENTED_EDGE('',*,*,#885,.T.);
#2171=ORIENTED_EDGE('',*,*,#2156,.F.);
#2172=EDGE_LOOP('',(#2168,#2169,#2170,#2171));
#2173=FACE_BOUND('',#2172,.T.);
#2174=ADVANCED_FACE('F1119',(#2173),#2167,.F.);
#2175=CARTESIAN_POINT('',(20.4,-12.501,4.4));
#2176=DIRECTION('',(1.,0.,0.));
#2177=DIRECTION('',(0.,0.,-1.));
#2178=AXIS2_PLACEMENT_3D('',#2175,#2176,#2177);
#2179=PLANE('',#2178);
#2180=ORIENTED_EDGE('',*,*,#1077,.T.);
#2181=ORIENTED_EDGE('',*,*,#81,.T.);
#2182=ORIENTED_EDGE('',*,*,#914,.T.);
#2183=DIRECTION('',(0.,1.,0.));
#2184=VECTOR('',#2183,1.);
#2185=CARTESIAN_POINT('',(20.4,-12.501,3.6));
#2186=LINE('',#2185,#2184);
#2187=EDGE_CURVE('E933',#1076,#907,#2186,.T.);
#2188=ORIENTED_EDGE('',*,*,#2187,.F.);
#2189=EDGE_LOOP('',(#2180,#2181,#2182,#2188));
#2190=FACE_BOUND('',#2189,.T.);
#2191=ADVANCED_FACE('F1636',(#2190),#2179,.F.);
#2192=CARTESIAN_POINT('',(19.6,-12.501,4.4));
#2193=DIRECTION('',(-1.,0.,0.));
#2194=DIRECTION('',(0.,0.,1.));
#2195=AXIS2_PLACEMENT_3D('',#2192,#2193,#2194);
#2196=PLANE('',#2195);
#2197=ORIENTED_EDGE('',*,*,#1091,.T.);
#2198=DIRECTION('',(0.,1.,0.));
#2199=VECTOR('',#2198,1.);
#2200=CARTESIAN_POINT('',(19.6,-12.501,3.6));
#2201=LINE('',#2200,#2199);
#2202=EDGE_CURVE('E932',#1084,#899,#2201,.T.);
#2203=ORIENTED_EDGE('',*,*,#2202,.T.);
#2204=ORIENTED_EDGE('',*,*,#900,.T.);
#2205=ORIENTED_EDGE('',*,*,#98,.T.);
#2206=EDGE_LOOP('',(#2197,#2203,#2204,#2205));
#2207=FACE_BOUND('',#2206,.T.);
#2208=ADVANCED_FACE('F1645',(#2207),#2196,.F.);
#2209=CARTESIAN_POINT('',(19.6,-12.501,3.6));
#2210=DIRECTION('',(0.,0.,-1.));
#2211=DIRECTION('',(-1.,0.,0.));
#2212=AXIS2_PLACEMENT_3D('',#2209,#2210,#2211);
#2213=PLANE('',#2212);
#2214=ORIENTED_EDGE('',*,*,#1085,.T.);
#2215=ORIENTED_EDGE('',*,*,#2187,.T.);
#2216=ORIENTED_EDGE('',*,*,#908,.T.);
#2217=ORIENTED_EDGE('',*,*,#2202,.F.);
#2218=EDGE_LOOP('',(#2214,#2215,#2216,#2217));
#2219=FACE_BOUND('',#2218,.T.);
#2220=ADVANCED_FACE('F1655',(#2219),#2213,.F.);
#2221=CARTESIAN_POINT('',(22.4,-12.501,4.4));
#2222=DIRECTION('',(1.,0.,0.));
#2223=DIRECTION('',(0.,0.,-1.));
#2224=AXIS2_PLACEMENT_3D('',#2221,#2222,#2223);
#2225=PLANE('',#2224);
#2226=ORIENTED_EDGE('',*,*,#1054,.T.);
#2227=ORIENTED_EDGE('',*,*,#40,.T.);
#2228=ORIENTED_EDGE('',*,*,#937,.T.);
#2229=DIRECTION('',(0.,1.,0.));
#2230=VECTOR('',#2229,1.);
#2231=CARTESIAN_POINT('',(22.4,-12.501,3.6));
#2232=LINE('',#2231,#2230);
#2233=EDGE_CURVE('E952',#1053,#930,#2232,.T.);
#2234=ORIENTED_EDGE('',*,*,#2233,.F.);
#2235=EDGE_LOOP('',(#2226,#2227,#2228,#2234));
#2236=FACE_BOUND('',#2235,.T.);
#2237=ADVANCED_FACE('F966',(#2236),#2225,.F.);
#2238=CARTESIAN_POINT('',(21.6,-12.501,4.4));
#2239=DIRECTION('',(-1.,0.,0.));
#2240=DIRECTION('',(0.,0.,1.));
#2241=AXIS2_PLACEMENT_3D('',#2238,#2239,#2240);
#2242=PLANE('',#2241);
#2243=ORIENTED_EDGE('',*,*,#1068,.T.);
#2244=DIRECTION('',(0.,1.,0.));
#2245=VECTOR('',#2244,1.);
#2246=CARTESIAN_POINT('',(21.6,-12.501,3.6));
#2247=LINE('',#2246,#2245);
#2248=EDGE_CURVE('E951',#1061,#922,#2247,.T.);
#2249=ORIENTED_EDGE('',*,*,#2248,.T.);
#2250=ORIENTED_EDGE('',*,*,#923,.T.);
#2251=ORIENTED_EDGE('',*,*,#71,.T.);
#2252=EDGE_LOOP('',(#2243,#2249,#2250,#2251));
#2253=FACE_BOUND('',#2252,.T.);
#2254=ADVANCED_FACE('F495',(#2253),#2242,.F.);
#2255=CARTESIAN_POINT('',(21.6,-12.501,3.6));
#2256=DIRECTION('',(0.,0.,-1.));
#2257=DIRECTION('',(-1.,0.,0.));
#2258=AXIS2_PLACEMENT_3D('',#2255,#2256,#2257);
#2259=PLANE('',#2258);
#2260=ORIENTED_EDGE('',*,*,#1062,.T.);
#2261=ORIENTED_EDGE('',*,*,#2233,.T.);
#2262=ORIENTED_EDGE('',*,*,#931,.T.);
#2263=ORIENTED_EDGE('',*,*,#2248,.F.);
#2264=EDGE_LOOP('',(#2260,#2261,#2262,#2263));
#2265=FACE_BOUND('',#2264,.T.);
#2266=ADVANCED_FACE('F1001',(#2265),#2259,.F.);
#2267=CARTESIAN_POINT('',(-25.,-12.5,0.57735026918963));
#2268=DIRECTION('',(-0.5,0.,-0.866025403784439));
#2269=DIRECTION('',(0.,1.,0.));
#2270=AXIS2_PLACEMENT_3D('',#2267,#2268,#2269);
#2271=PLANE('',#2270);
#2272=ORIENTED_EDGE('',*,*,#581,.F.);
#2273=ORIENTED_EDGE('',*,*,#485,.F.);
#2274=ORIENTED_EDGE('',*,*,#1014,.F.);
#2275=ORIENTED_EDGE('',*,*,#985,.F.);
#2276=EDGE_LOOP('',(#2272,#2273,#2274,#2275));
#2277=FACE_BOUND('',#2276,.T.);
#2278=ADVANCED_FACE('F36',(#2277),#2271,.T.);
#2279=CLOSED_SHELL('',(#58,#85,#112,#139,#166,#193,#220,#247,#274,#301,#328,#355,#382,#409,#436,
#463,#537,#568,#972,#1003,#1398,#1410,#1422,#1453,#1477,#1501,#1518,#1530,#1547,#1564,#1576,
#1593,#1610,#1622,#1639,#1656,#1668,#1685,#1702,#1714,#1731,#1748,#1760,#1777,#1794,#1806,#1823,
#1840,#1852,#1869,#1886,#1898,#1915,#1932,#1944,#1961,#1978,#1990,#2007,#2024,#2036,#2053,#2070,
#2082,#2099,#2116,#2128,#2145,#2162,#2174,#2191,#2208,#2220,#2237,#2254,#2266,#2278));
#2280=MANIFOLD_SOLID_BREP('B2',#2279);
#2281=ADVANCED_BREP_SHAPE_REPRESENTATION('',(#18,#2280),#14);
#2282=SHAPE_DEFINITION_REPRESENTATION(#9,#2281);
ENDSEC;
END-ISO-10303-21;
